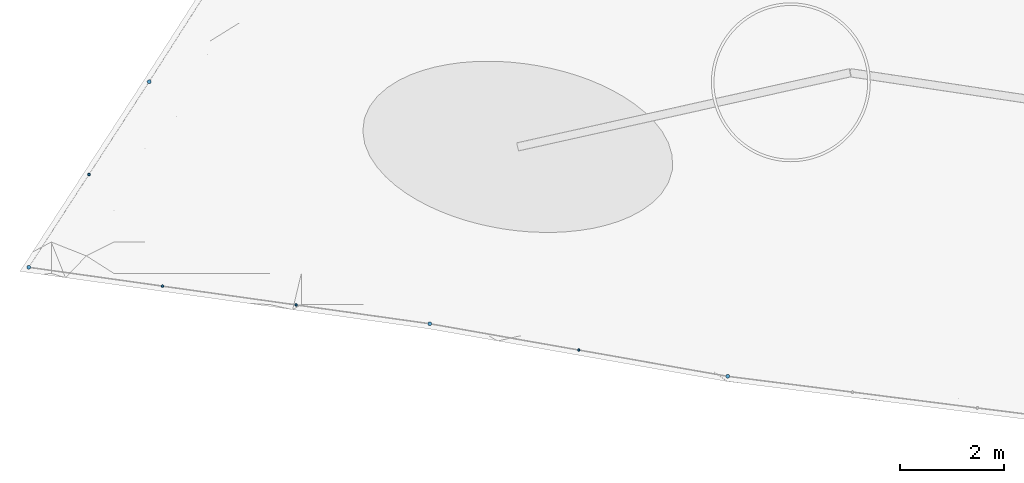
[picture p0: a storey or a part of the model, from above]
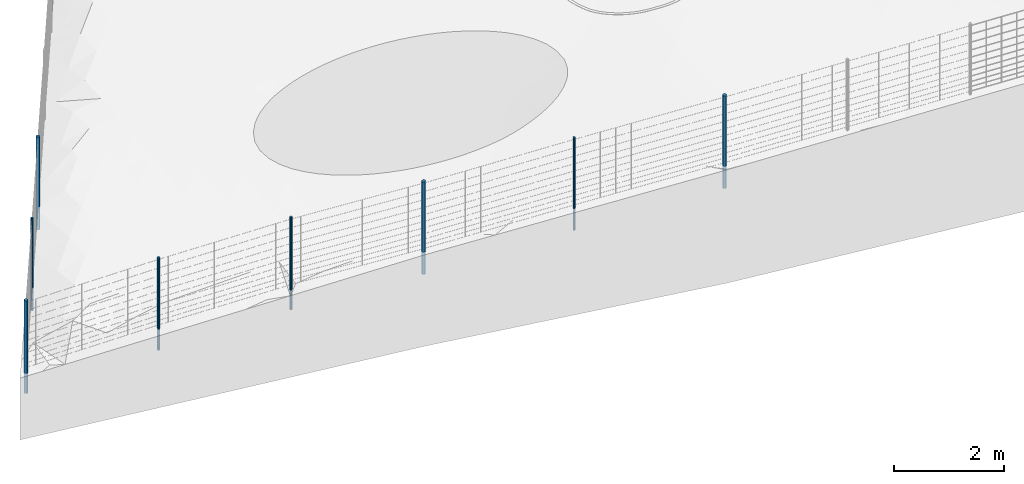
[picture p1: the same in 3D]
Properties of the parts of a building model (IFC4), part 1 of 3

# File
Description: ViewDefinition [CoordinationView]
File name: Casa_Sobreposta_Implantada.ifc
Time: 2026-10-02T16:19:36
Written by: IfcOpenShell 0.8.0
Made in: IfcOpenShell 0.8.0

# IfcProject, Casa / Lares · R09 · Estufa
Pset_CasaModel - Design: R09 / estufa / lower hybrid podium and ground-supported parking; ReferenceFile: 260617_CasaDFL_Estrutura_Terreno.ifc; ModelStatus: DESIGN_STUDY; North: Survey grid +Y; Ramp: No exterior pedestrian ramp or vehicular bridge; EngineeringStatus: Member sizes, foundations, connections, bracing and environmental performance not verified; GroundFFL_m: 14.65; AreaLimit_m2: 250; CountedGeometricArea_m2: 181.073; GreenhouseExcludedByUser: yes; UpperFinishedFloor_m: 17.89; BalconiesExcludedByClient: yes; CoveredGroundBalcony_m2: 56.7788; PlanningComplianceEstablished: no; AreaBasis: Client-confirmed 250 m2 allowance: parking, cistern, balconies and open greenhouse excluded; enclosed upper rooms and stair enclosures count. Any storage would count. Geometric study, no independent PDM verification.

# IfcSite, Lares · Rua das Mercês · artigo 4771
Pset_SurveySource - File: GN_09.26_213 Lares.dwg; SHA256: 0bca0a0751148bad1398f92d81b795428f94a57fea5e37dec0e125cea70402a1; Area_m2: 1636.5; BoundaryHandle: 31B; CoordinateReference: PT-TM06 / ETRS89; TerrainStatus: Proposed grading; original survey in separate IFC

# IfcBuilding, Casa Sobreposta
Pset_CasaFloorAssembly - UpperFFL_m: 3.24; JoistUnderside_m: 2.968; JoistDepth_m: 0.24; OSB_m: 0.02; Membrane_m: 0.002; ProtectiveFinish_m: 0.01; Basis: TJI240 + OSB20 from reference; greenhouse waterproofing/finish assumed; imposed loads unverified
Pset_CasaPlacement - GroundFloorSurveyLevel_m: 14.65; UpperFloor: yes; MoveEast_m: 3; MoveSouth_m: 0.5; RotationFromGridEast_deg: -8.5; BoundarySetbackRequired_m: 3; RuleBasis: User project constraint
Pset_CasaRevision09 - Variant: estufa; HybridPodium: yes; ParkingGroundSupported: yes; GroundFFL_m: 14.65; TerraceFFL_m: 14.61; VehicularBridgeLength_m: 0; AccessGabions: no; Cut_m3: 96.4024; Fill_m3: 5.19635; EarthworkExclusions: Topsoil, foundation/service trenches, soil replacement, construction working space and bulking; CoveredGroundBalconyClassification: EXCLUDED_BY_CLIENT; WindCapacityVerified: no

# IfcBuildingStorey (3)
In: Casa Sobreposta
Name | Elevation (m)
00 · Habitação e estacionamento | 14.65
01 · Jardim de inverno | 17.89
-01 · Cisterna sob o terraço | 12.05

# IfcSpace (18)
Pset_CasaProvenance - DesignSource: Casa Sobreposta / configuration.json; ReferenceFile: 260617_CasaDFL_Estrutura_Terreno.ifc; ConstructionBasis: DESIGN_ASSUMPTION; Note: Functional zone from configurator; overlaps with partition footprints removed on ground floor. Not certified usable floor area.
Name | In | PredefinedType | NetFloorArea (m2)
Sala | 00 · Habitação e estacionamento | INTERNAL | 31.359
Cozinha | 00 · Habitação e estacionamento | INTERNAL | 9.94248
Banho | 00 · Habitação e estacionamento | INTERNAL | 7.19804
WC | 00 · Habitação e estacionamento | INTERNAL | 1.231
Serviço | 00 · Habitação e estacionamento | INTERNAL | 4.16058
Acesso IS | 00 · Habitação e estacionamento | INTERNAL | 3.99017
Quarto 1 | 00 · Habitação e estacionamento | INTERNAL | 13.1145
Quarto 2 | 00 · Habitação e estacionamento | INTERNAL | 13.1145
Quarto / escritório | 00 · Habitação e estacionamento | INTERNAL | 37.8909
Circulação | 00 · Habitação e estacionamento | INTERNAL | 18.1139
Estacionamento · 2 lugares | 00 · Habitação e estacionamento | EXTERNAL | 32.55
Galeria sul · balanço 1,50 m | 01 · Jardim de inverno | INTERNAL | 48
Jardim de inverno | 01 · Jardim de inverno | INTERNAL | 47.852
Circulação / estar | 01 · Jardim de inverno | INTERNAL | 68.8278
Banho superior | 01 · Jardim de inverno | INTERNAL | 7.3678
Cultivo / jardim | 01 · Jardim de inverno | INTERNAL | 25.5734
Estar sobre a garagem | 01 · Jardim de inverno | INTERNAL | 21.292
Balanço | 01 · Jardim de inverno | INTERNAL | 25.6

# IfcAnnotation (4)
Pset_CasaProvenance - DesignSource: Casa Sobreposta / configuration.json; ReferenceFile: 260617_CasaDFL_Estrutura_Terreno.ifc; ConstructionBasis: DESIGN_ASSUMPTION
Name | In
Lugar P1 · 2.50 x 5.00 m | 00 · Habitação e estacionamento
Lugar P2 · 2.50 x 5.00 m | 00 · Habitação e estacionamento
Limite levantado · 31B | Lares · Rua das Mercês · artigo 4771
Afastamento de implantação · 3 m | Lares · Rua das Mercês · artigo 4771

# IfcBeam (115)
Pset_CasaProvenance - DesignSource: Casa Sobreposta / configuration.json; ReferenceFile: 260617_CasaDFL_Estrutura_Terreno.ifc
Name | In | Material | ConstructionBasis | Note
TJI240 · 0.065 / -1.15 | 01 · Jardim de inverno | Madeira / Bauholz (2), OSB | ADAPTED_REFERENCE | Composite wood flanges + OSB web; 600 mm study spacing. Reference 44.45 mm width / 9.525 mm web; flanges regularised to 28 mm. Not structurally sized.
TJI240 · 4.065 / -1.15 | 01 · Jardim de inverno | Madeira / Bauholz (2), OSB | ADAPTED_REFERENCE | Composite wood flanges + OSB web; 600 mm study spacing. Reference 44.45 mm width / 9.525 mm web; flanges regularised to 28 mm. Not structurally sized.
TJI240 · 8.065 / -1.15 | 01 · Jardim de inverno | Madeira / Bauholz (2), OSB | ADAPTED_REFERENCE | Composite wood flanges + OSB web; 600 mm study spacing. Reference 44.45 mm width / 9.525 mm web; flanges regularised to 28 mm. Not structurally sized.
TJI240 · 12.065 / -1.15 | 01 · Jardim de inverno | Madeira / Bauholz (2), OSB | ADAPTED_REFERENCE | Composite wood flanges + OSB web; 600 mm study spacing. Reference 44.45 mm width / 9.525 mm web; flanges regularised to 28 mm. Not structurally sized.
TJI240 · 16.065 / -1.15 | 01 · Jardim de inverno | Madeira / Bauholz (2), OSB | ADAPTED_REFERENCE | Composite wood flanges + OSB web; 600 mm study spacing. Reference 44.45 mm width / 9.525 mm web; flanges regularised to 28 mm. Not structurally sized.
TJI240 · 20.065 / -1.15 | 01 · Jardim de inverno | Madeira / Bauholz (2), OSB | ADAPTED_REFERENCE | Composite wood flanges + OSB web; 600 mm study spacing. Reference 44.45 mm width / 9.525 mm web; flanges regularised to 28 mm. Not structurally sized.
TJI240 · 24.065 / -1.15 | 01 · Jardim de inverno | Madeira / Bauholz (2), OSB | ADAPTED_REFERENCE | Composite wood flanges + OSB web; 600 mm study spacing. Reference 44.45 mm width / 9.525 mm web; flanges regularised to 28 mm. Not structurally sized.
TJI240 · 28.065 / -1.15 | 01 · Jardim de inverno | Madeira / Bauholz (2), OSB | ADAPTED_REFERENCE | Composite wood flanges + OSB web; 600 mm study spacing. Reference 44.45 mm width / 9.525 mm web; flanges regularised to 28 mm. Not structurally sized.
TJI240 · 0.065 / -0.55 | 01 · Jardim de inverno | Madeira / Bauholz (2), OSB | ADAPTED_REFERENCE | Composite wood flanges + OSB web; 600 mm study spacing. Reference 44.45 mm width / 9.525 mm web; flanges regularised to 28 mm. Not structurally sized.
TJI240 · 4.065 / -0.55 | 01 · Jardim de inverno | Madeira / Bauholz (2), OSB | ADAPTED_REFERENCE | Composite wood flanges + OSB web; 600 mm study spacing. Reference 44.45 mm width / 9.525 mm web; flanges regularised to 28 mm. Not structurally sized.
TJI240 · 8.065 / -0.55 | 01 · Jardim de inverno | Madeira / Bauholz (2), OSB | ADAPTED_REFERENCE | Composite wood flanges + OSB web; 600 mm study spacing. Reference 44.45 mm width / 9.525 mm web; flanges regularised to 28 mm. Not structurally sized.
TJI240 · 12.065 / -0.55 | 01 · Jardim de inverno | Madeira / Bauholz (2), OSB | ADAPTED_REFERENCE | Composite wood flanges + OSB web; 600 mm study spacing. Reference 44.45 mm width / 9.525 mm web; flanges regularised to 28 mm. Not structurally sized.
TJI240 · 16.065 / -0.55 | 01 · Jardim de inverno | Madeira / Bauholz (2), OSB | ADAPTED_REFERENCE | Composite wood flanges + OSB web; 600 mm study spacing. Reference 44.45 mm width / 9.525 mm web; flanges regularised to 28 mm. Not structurally sized.
TJI240 · 20.065 / -0.55 | 01 · Jardim de inverno | Madeira / Bauholz (2), OSB | ADAPTED_REFERENCE | Composite wood flanges + OSB web; 600 mm study spacing. Reference 44.45 mm width / 9.525 mm web; flanges regularised to 28 mm. Not structurally sized.
TJI240 · 24.065 / -0.55 | 01 · Jardim de inverno | Madeira / Bauholz (2), OSB | ADAPTED_REFERENCE | Composite wood flanges + OSB web; 600 mm study spacing. Reference 44.45 mm width / 9.525 mm web; flanges regularised to 28 mm. Not structurally sized.
TJI240 · 28.065 / -0.55 | 01 · Jardim de inverno | Madeira / Bauholz (2), OSB | ADAPTED_REFERENCE | Composite wood flanges + OSB web; 600 mm study spacing. Reference 44.45 mm width / 9.525 mm web; flanges regularised to 28 mm. Not structurally sized.
TJI240 · 0.065 / 0.05 | 01 · Jardim de inverno | Madeira / Bauholz (2), OSB | ADAPTED_REFERENCE | Composite wood flanges + OSB web; 600 mm study spacing. Reference 44.45 mm width / 9.525 mm web; flanges regularised to 28 mm. Not structurally sized.
TJI240 · 4.065 / 0.05 | 01 · Jardim de inverno | Madeira / Bauholz (2), OSB | ADAPTED_REFERENCE | Composite wood flanges + OSB web; 600 mm study spacing. Reference 44.45 mm width / 9.525 mm web; flanges regularised to 28 mm. Not structurally sized.
TJI240 · 8.065 / 0.05 | 01 · Jardim de inverno | Madeira / Bauholz (2), OSB | ADAPTED_REFERENCE | Composite wood flanges + OSB web; 600 mm study spacing. Reference 44.45 mm width / 9.525 mm web; flanges regularised to 28 mm. Not structurally sized.
TJI240 · 12.065 / 0.05 | 01 · Jardim de inverno | Madeira / Bauholz (2), OSB | ADAPTED_REFERENCE | Composite wood flanges + OSB web; 600 mm study spacing. Reference 44.45 mm width / 9.525 mm web; flanges regularised to 28 mm. Not structurally sized.
TJI240 · 16.065 / 0.05 | 01 · Jardim de inverno | Madeira / Bauholz (2), OSB | ADAPTED_REFERENCE | Composite wood flanges + OSB web; 600 mm study spacing. Reference 44.45 mm width / 9.525 mm web; flanges regularised to 28 mm. Not structurally sized.
TJI240 · 20.065 / 0.05 | 01 · Jardim de inverno | Madeira / Bauholz (2), OSB | ADAPTED_REFERENCE | Composite wood flanges + OSB web; 600 mm study spacing. Reference 44.45 mm width / 9.525 mm web; flanges regularised to 28 mm. Not structurally sized.
TJI240 · 24.065 / 0.05 | 01 · Jardim de inverno | Madeira / Bauholz (2), OSB | ADAPTED_REFERENCE | Composite wood flanges + OSB web; 600 mm study spacing. Reference 44.45 mm width / 9.525 mm web; flanges regularised to 28 mm. Not structurally sized.
TJI240 · 28.065 / 0.05 | 01 · Jardim de inverno | Madeira / Bauholz (2), OSB | ADAPTED_REFERENCE | Composite wood flanges + OSB web; 600 mm study spacing. Reference 44.45 mm width / 9.525 mm web; flanges regularised to 28 mm. Not structurally sized.
TJI240 · 0.065 / 0.65 | 01 · Jardim de inverno | Madeira / Bauholz (2), OSB | ADAPTED_REFERENCE | Composite wood flanges + OSB web; 600 mm study spacing. Reference 44.45 mm width / 9.525 mm web; flanges regularised to 28 mm. Not structurally sized.
TJI240 · 4.065 / 0.65 | 01 · Jardim de inverno | Madeira / Bauholz (2), OSB | ADAPTED_REFERENCE | Composite wood flanges + OSB web; 600 mm study spacing. Reference 44.45 mm width / 9.525 mm web; flanges regularised to 28 mm. Not structurally sized.
TJI240 · 8.065 / 0.65 | 01 · Jardim de inverno | Madeira / Bauholz (2), OSB | ADAPTED_REFERENCE | Composite wood flanges + OSB web; 600 mm study spacing. Reference 44.45 mm width / 9.525 mm web; flanges regularised to 28 mm. Not structurally sized.
TJI240 · 12.065 / 0.65 | 01 · Jardim de inverno | Madeira / Bauholz (2), OSB | ADAPTED_REFERENCE | Composite wood flanges + OSB web; 600 mm study spacing. Reference 44.45 mm width / 9.525 mm web; flanges regularised to 28 mm. Not structurally sized.
TJI240 · 16.065 / 0.65 | 01 · Jardim de inverno | Madeira / Bauholz (2), OSB | ADAPTED_REFERENCE | Composite wood flanges + OSB web; 600 mm study spacing. Reference 44.45 mm width / 9.525 mm web; flanges regularised to 28 mm. Not structurally sized.
TJI240 · 20.065 / 0.65 | 01 · Jardim de inverno | Madeira / Bauholz (2), OSB | ADAPTED_REFERENCE | Composite wood flanges + OSB web; 600 mm study spacing. Reference 44.45 mm width / 9.525 mm web; flanges regularised to 28 mm. Not structurally sized.
TJI240 · 24.065 / 0.65 | 01 · Jardim de inverno | Madeira / Bauholz (2), OSB | ADAPTED_REFERENCE | Composite wood flanges + OSB web; 600 mm study spacing. Reference 44.45 mm width / 9.525 mm web; flanges regularised to 28 mm. Not structurally sized.
TJI240 · 28.065 / 0.65 | 01 · Jardim de inverno | Madeira / Bauholz (2), OSB | ADAPTED_REFERENCE | Composite wood flanges + OSB web; 600 mm study spacing. Reference 44.45 mm width / 9.525 mm web; flanges regularised to 28 mm. Not structurally sized.
TJI240 · 0.970 / 1.25 | 01 · Jardim de inverno | Madeira / Bauholz (2), OSB | ADAPTED_REFERENCE | Composite wood flanges + OSB web; 600 mm study spacing. Reference 44.45 mm width / 9.525 mm web; flanges regularised to 28 mm. Not structurally sized.
TJI240 · 4.065 / 1.25 | 01 · Jardim de inverno | Madeira / Bauholz (2), OSB | ADAPTED_REFERENCE | Composite wood flanges + OSB web; 600 mm study spacing. Reference 44.45 mm width / 9.525 mm web; flanges regularised to 28 mm. Not structurally sized.
TJI240 · 8.065 / 1.25 | 01 · Jardim de inverno | Madeira / Bauholz (2), OSB | ADAPTED_REFERENCE | Composite wood flanges + OSB web; 600 mm study spacing. Reference 44.45 mm width / 9.525 mm web; flanges regularised to 28 mm. Not structurally sized.
TJI240 · 12.065 / 1.25 | 01 · Jardim de inverno | Madeira / Bauholz (2), OSB | ADAPTED_REFERENCE | Composite wood flanges + OSB web; 600 mm study spacing. Reference 44.45 mm width / 9.525 mm web; flanges regularised to 28 mm. Not structurally sized.
TJI240 · 16.065 / 1.25 | 01 · Jardim de inverno | Madeira / Bauholz (2), OSB | ADAPTED_REFERENCE | Composite wood flanges + OSB web; 600 mm study spacing. Reference 44.45 mm width / 9.525 mm web; flanges regularised to 28 mm. Not structurally sized.
TJI240 · 20.065 / 1.25 | 01 · Jardim de inverno | Madeira / Bauholz (2), OSB | ADAPTED_REFERENCE | Composite wood flanges + OSB web; 600 mm study spacing. Reference 44.45 mm width / 9.525 mm web; flanges regularised to 28 mm. Not structurally sized.
TJI240 · 25.040 / 1.25 | 01 · Jardim de inverno | Madeira / Bauholz (2), OSB | ADAPTED_REFERENCE | Composite wood flanges + OSB web; 600 mm study spacing. Reference 44.45 mm width / 9.525 mm web; flanges regularised to 28 mm. Not structurally sized.
TJI240 · 28.065 / 1.25 | 01 · Jardim de inverno | Madeira / Bauholz (2), OSB | ADAPTED_REFERENCE | Composite wood flanges + OSB web; 600 mm study spacing. Reference 44.45 mm width / 9.525 mm web; flanges regularised to 28 mm. Not structurally sized.
TJI240 · 0.970 / 1.85 | 01 · Jardim de inverno | Madeira / Bauholz (2), OSB | ADAPTED_REFERENCE | Composite wood flanges + OSB web; 600 mm study spacing. Reference 44.45 mm width / 9.525 mm web; flanges regularised to 28 mm. Not structurally sized.
TJI240 · 4.065 / 1.85 | 01 · Jardim de inverno | Madeira / Bauholz (2), OSB | ADAPTED_REFERENCE | Composite wood flanges + OSB web; 600 mm study spacing. Reference 44.45 mm width / 9.525 mm web; flanges regularised to 28 mm. Not structurally sized.
TJI240 · 8.065 / 1.85 | 01 · Jardim de inverno | Madeira / Bauholz (2), OSB | ADAPTED_REFERENCE | Composite wood flanges + OSB web; 600 mm study spacing. Reference 44.45 mm width / 9.525 mm web; flanges regularised to 28 mm. Not structurally sized.
TJI240 · 12.065 / 1.85 | 01 · Jardim de inverno | Madeira / Bauholz (2), OSB | ADAPTED_REFERENCE | Composite wood flanges + OSB web; 600 mm study spacing. Reference 44.45 mm width / 9.525 mm web; flanges regularised to 28 mm. Not structurally sized.
TJI240 · 16.065 / 1.85 | 01 · Jardim de inverno | Madeira / Bauholz (2), OSB | ADAPTED_REFERENCE | Composite wood flanges + OSB web; 600 mm study spacing. Reference 44.45 mm width / 9.525 mm web; flanges regularised to 28 mm. Not structurally sized.
TJI240 · 20.065 / 1.85 | 01 · Jardim de inverno | Madeira / Bauholz (2), OSB | ADAPTED_REFERENCE | Composite wood flanges + OSB web; 600 mm study spacing. Reference 44.45 mm width / 9.525 mm web; flanges regularised to 28 mm. Not structurally sized.
TJI240 · 25.040 / 1.85 | 01 · Jardim de inverno | Madeira / Bauholz (2), OSB | ADAPTED_REFERENCE | Composite wood flanges + OSB web; 600 mm study spacing. Reference 44.45 mm width / 9.525 mm web; flanges regularised to 28 mm. Not structurally sized.
TJI240 · 28.065 / 1.85 | 01 · Jardim de inverno | Madeira / Bauholz (2), OSB | ADAPTED_REFERENCE | Composite wood flanges + OSB web; 600 mm study spacing. Reference 44.45 mm width / 9.525 mm web; flanges regularised to 28 mm. Not structurally sized.
TJI240 · 0.970 / 2.45 | 01 · Jardim de inverno | Madeira / Bauholz (2), OSB | ADAPTED_REFERENCE | Composite wood flanges + OSB web; 600 mm study spacing. Reference 44.45 mm width / 9.525 mm web; flanges regularised to 28 mm. Not structurally sized.
TJI240 · 4.065 / 2.45 | 01 · Jardim de inverno | Madeira / Bauholz (2), OSB | ADAPTED_REFERENCE | Composite wood flanges + OSB web; 600 mm study spacing. Reference 44.45 mm width / 9.525 mm web; flanges regularised to 28 mm. Not structurally sized.
TJI240 · 8.065 / 2.45 | 01 · Jardim de inverno | Madeira / Bauholz (2), OSB | ADAPTED_REFERENCE | Composite wood flanges + OSB web; 600 mm study spacing. Reference 44.45 mm width / 9.525 mm web; flanges regularised to 28 mm. Not structurally sized.
TJI240 · 12.065 / 2.45 | 01 · Jardim de inverno | Madeira / Bauholz (2), OSB | ADAPTED_REFERENCE | Composite wood flanges + OSB web; 600 mm study spacing. Reference 44.45 mm width / 9.525 mm web; flanges regularised to 28 mm. Not structurally sized.
TJI240 · 16.065 / 2.45 | 01 · Jardim de inverno | Madeira / Bauholz (2), OSB | ADAPTED_REFERENCE | Composite wood flanges + OSB web; 600 mm study spacing. Reference 44.45 mm width / 9.525 mm web; flanges regularised to 28 mm. Not structurally sized.
TJI240 · 20.065 / 2.45 | 01 · Jardim de inverno | Madeira / Bauholz (2), OSB | ADAPTED_REFERENCE | Composite wood flanges + OSB web; 600 mm study spacing. Reference 44.45 mm width / 9.525 mm web; flanges regularised to 28 mm. Not structurally sized.
TJI240 · 25.040 / 2.45 | 01 · Jardim de inverno | Madeira / Bauholz (2), OSB | ADAPTED_REFERENCE | Composite wood flanges + OSB web; 600 mm study spacing. Reference 44.45 mm width / 9.525 mm web; flanges regularised to 28 mm. Not structurally sized.
TJI240 · 28.065 / 2.45 | 01 · Jardim de inverno | Madeira / Bauholz (2), OSB | ADAPTED_REFERENCE | Composite wood flanges + OSB web; 600 mm study spacing. Reference 44.45 mm width / 9.525 mm web; flanges regularised to 28 mm. Not structurally sized.
TJI240 · 0.970 / 3.05 | 01 · Jardim de inverno | Madeira / Bauholz (2), OSB | ADAPTED_REFERENCE | Composite wood flanges + OSB web; 600 mm study spacing. Reference 44.45 mm width / 9.525 mm web; flanges regularised to 28 mm. Not structurally sized.
TJI240 · 4.065 / 3.05 | 01 · Jardim de inverno | Madeira / Bauholz (2), OSB | ADAPTED_REFERENCE | Composite wood flanges + OSB web; 600 mm study spacing. Reference 44.45 mm width / 9.525 mm web; flanges regularised to 28 mm. Not structurally sized.
TJI240 · 8.065 / 3.05 | 01 · Jardim de inverno | Madeira / Bauholz (2), OSB | ADAPTED_REFERENCE | Composite wood flanges + OSB web; 600 mm study spacing. Reference 44.45 mm width / 9.525 mm web; flanges regularised to 28 mm. Not structurally sized.
TJI240 · 12.065 / 3.05 | 01 · Jardim de inverno | Madeira / Bauholz (2), OSB | ADAPTED_REFERENCE | Composite wood flanges + OSB web; 600 mm study spacing. Reference 44.45 mm width / 9.525 mm web; flanges regularised to 28 mm. Not structurally sized.
TJI240 · 16.065 / 3.05 | 01 · Jardim de inverno | Madeira / Bauholz (2), OSB | ADAPTED_REFERENCE | Composite wood flanges + OSB web; 600 mm study spacing. Reference 44.45 mm width / 9.525 mm web; flanges regularised to 28 mm. Not structurally sized.
TJI240 · 20.065 / 3.05 | 01 · Jardim de inverno | Madeira / Bauholz (2), OSB | ADAPTED_REFERENCE | Composite wood flanges + OSB web; 600 mm study spacing. Reference 44.45 mm width / 9.525 mm web; flanges regularised to 28 mm. Not structurally sized.
TJI240 · 25.040 / 3.05 | 01 · Jardim de inverno | Madeira / Bauholz (2), OSB | ADAPTED_REFERENCE | Composite wood flanges + OSB web; 600 mm study spacing. Reference 44.45 mm width / 9.525 mm web; flanges regularised to 28 mm. Not structurally sized.
TJI240 · 28.065 / 3.05 | 01 · Jardim de inverno | Madeira / Bauholz (2), OSB | ADAPTED_REFERENCE | Composite wood flanges + OSB web; 600 mm study spacing. Reference 44.45 mm width / 9.525 mm web; flanges regularised to 28 mm. Not structurally sized.
TJI240 · 0.970 / 3.65 | 01 · Jardim de inverno | Madeira / Bauholz (2), OSB | ADAPTED_REFERENCE | Composite wood flanges + OSB web; 600 mm study spacing. Reference 44.45 mm width / 9.525 mm web; flanges regularised to 28 mm. Not structurally sized.
TJI240 · 4.065 / 3.65 | 01 · Jardim de inverno | Madeira / Bauholz (2), OSB | ADAPTED_REFERENCE | Composite wood flanges + OSB web; 600 mm study spacing. Reference 44.45 mm width / 9.525 mm web; flanges regularised to 28 mm. Not structurally sized.
TJI240 · 8.065 / 3.65 | 01 · Jardim de inverno | Madeira / Bauholz (2), OSB | ADAPTED_REFERENCE | Composite wood flanges + OSB web; 600 mm study spacing. Reference 44.45 mm width / 9.525 mm web; flanges regularised to 28 mm. Not structurally sized.
TJI240 · 12.065 / 3.65 | 01 · Jardim de inverno | Madeira / Bauholz (2), OSB | ADAPTED_REFERENCE | Composite wood flanges + OSB web; 600 mm study spacing. Reference 44.45 mm width / 9.525 mm web; flanges regularised to 28 mm. Not structurally sized.
TJI240 · 16.065 / 3.65 | 01 · Jardim de inverno | Madeira / Bauholz (2), OSB | ADAPTED_REFERENCE | Composite wood flanges + OSB web; 600 mm study spacing. Reference 44.45 mm width / 9.525 mm web; flanges regularised to 28 mm. Not structurally sized.
TJI240 · 20.065 / 3.65 | 01 · Jardim de inverno | Madeira / Bauholz (2), OSB | ADAPTED_REFERENCE | Composite wood flanges + OSB web; 600 mm study spacing. Reference 44.45 mm width / 9.525 mm web; flanges regularised to 28 mm. Not structurally sized.
TJI240 · 25.040 / 3.65 | 01 · Jardim de inverno | Madeira / Bauholz (2), OSB | ADAPTED_REFERENCE | Composite wood flanges + OSB web; 600 mm study spacing. Reference 44.45 mm width / 9.525 mm web; flanges regularised to 28 mm. Not structurally sized.
TJI240 · 28.065 / 3.65 | 01 · Jardim de inverno | Madeira / Bauholz (2), OSB | ADAPTED_REFERENCE | Composite wood flanges + OSB web; 600 mm study spacing. Reference 44.45 mm width / 9.525 mm web; flanges regularised to 28 mm. Not structurally sized.
TJI240 · 0.970 / 4.25 | 01 · Jardim de inverno | Madeira / Bauholz (2), OSB | ADAPTED_REFERENCE | Composite wood flanges + OSB web; 600 mm study spacing. Reference 44.45 mm width / 9.525 mm web; flanges regularised to 28 mm. Not structurally sized.
TJI240 · 4.065 / 4.25 | 01 · Jardim de inverno | Madeira / Bauholz (2), OSB | ADAPTED_REFERENCE | Composite wood flanges + OSB web; 600 mm study spacing. Reference 44.45 mm width / 9.525 mm web; flanges regularised to 28 mm. Not structurally sized.
TJI240 · 8.065 / 4.25 | 01 · Jardim de inverno | Madeira / Bauholz (2), OSB | ADAPTED_REFERENCE | Composite wood flanges + OSB web; 600 mm study spacing. Reference 44.45 mm width / 9.525 mm web; flanges regularised to 28 mm. Not structurally sized.
TJI240 · 12.065 / 4.25 | 01 · Jardim de inverno | Madeira / Bauholz (2), OSB | ADAPTED_REFERENCE | Composite wood flanges + OSB web; 600 mm study spacing. Reference 44.45 mm width / 9.525 mm web; flanges regularised to 28 mm. Not structurally sized.
TJI240 · 16.065 / 4.25 | 01 · Jardim de inverno | Madeira / Bauholz (2), OSB | ADAPTED_REFERENCE | Composite wood flanges + OSB web; 600 mm study spacing. Reference 44.45 mm width / 9.525 mm web; flanges regularised to 28 mm. Not structurally sized.
TJI240 · 20.065 / 4.25 | 01 · Jardim de inverno | Madeira / Bauholz (2), OSB | ADAPTED_REFERENCE | Composite wood flanges + OSB web; 600 mm study spacing. Reference 44.45 mm width / 9.525 mm web; flanges regularised to 28 mm. Not structurally sized.
TJI240 · 25.040 / 4.25 | 01 · Jardim de inverno | Madeira / Bauholz (2), OSB | ADAPTED_REFERENCE | Composite wood flanges + OSB web; 600 mm study spacing. Reference 44.45 mm width / 9.525 mm web; flanges regularised to 28 mm. Not structurally sized.
TJI240 · 28.065 / 4.25 | 01 · Jardim de inverno | Madeira / Bauholz (2), OSB | ADAPTED_REFERENCE | Composite wood flanges + OSB web; 600 mm study spacing. Reference 44.45 mm width / 9.525 mm web; flanges regularised to 28 mm. Not structurally sized.
TJI240 · 0.970 / 4.85 | 01 · Jardim de inverno | Madeira / Bauholz (2), OSB | ADAPTED_REFERENCE | Composite wood flanges + OSB web; 600 mm study spacing. Reference 44.45 mm width / 9.525 mm web; flanges regularised to 28 mm. Not structurally sized.
TJI240 · 4.065 / 4.85 | 01 · Jardim de inverno | Madeira / Bauholz (2), OSB | ADAPTED_REFERENCE | Composite wood flanges + OSB web; 600 mm study spacing. Reference 44.45 mm width / 9.525 mm web; flanges regularised to 28 mm. Not structurally sized.
TJI240 · 8.065 / 4.85 | 01 · Jardim de inverno | Madeira / Bauholz (2), OSB | ADAPTED_REFERENCE | Composite wood flanges + OSB web; 600 mm study spacing. Reference 44.45 mm width / 9.525 mm web; flanges regularised to 28 mm. Not structurally sized.
TJI240 · 12.065 / 4.85 | 01 · Jardim de inverno | Madeira / Bauholz (2), OSB | ADAPTED_REFERENCE | Composite wood flanges + OSB web; 600 mm study spacing. Reference 44.45 mm width / 9.525 mm web; flanges regularised to 28 mm. Not structurally sized.
TJI240 · 16.065 / 4.85 | 01 · Jardim de inverno | Madeira / Bauholz (2), OSB | ADAPTED_REFERENCE | Composite wood flanges + OSB web; 600 mm study spacing. Reference 44.45 mm width / 9.525 mm web; flanges regularised to 28 mm. Not structurally sized.
TJI240 · 20.065 / 4.85 | 01 · Jardim de inverno | Madeira / Bauholz (2), OSB | ADAPTED_REFERENCE | Composite wood flanges + OSB web; 600 mm study spacing. Reference 44.45 mm width / 9.525 mm web; flanges regularised to 28 mm. Not structurally sized.
TJI240 · 25.040 / 4.85 | 01 · Jardim de inverno | Madeira / Bauholz (2), OSB | ADAPTED_REFERENCE | Composite wood flanges + OSB web; 600 mm study spacing. Reference 44.45 mm width / 9.525 mm web; flanges regularised to 28 mm. Not structurally sized.
TJI240 · 28.065 / 4.85 | 01 · Jardim de inverno | Madeira / Bauholz (2), OSB | ADAPTED_REFERENCE | Composite wood flanges + OSB web; 600 mm study spacing. Reference 44.45 mm width / 9.525 mm web; flanges regularised to 28 mm. Not structurally sized.
TJI240 · 0.970 / 5.45 | 01 · Jardim de inverno | Madeira / Bauholz (2), OSB | ADAPTED_REFERENCE | Composite wood flanges + OSB web; 600 mm study spacing. Reference 44.45 mm width / 9.525 mm web; flanges regularised to 28 mm. Not structurally sized.
TJI240 · 4.065 / 5.45 | 01 · Jardim de inverno | Madeira / Bauholz (2), OSB | ADAPTED_REFERENCE | Composite wood flanges + OSB web; 600 mm study spacing. Reference 44.45 mm width / 9.525 mm web; flanges regularised to 28 mm. Not structurally sized.
TJI240 · 8.065 / 5.45 | 01 · Jardim de inverno | Madeira / Bauholz (2), OSB | ADAPTED_REFERENCE | Composite wood flanges + OSB web; 600 mm study spacing. Reference 44.45 mm width / 9.525 mm web; flanges regularised to 28 mm. Not structurally sized.
TJI240 · 12.065 / 5.45 | 01 · Jardim de inverno | Madeira / Bauholz (2), OSB | ADAPTED_REFERENCE | Composite wood flanges + OSB web; 600 mm study spacing. Reference 44.45 mm width / 9.525 mm web; flanges regularised to 28 mm. Not structurally sized.
TJI240 · 16.065 / 5.45 | 01 · Jardim de inverno | Madeira / Bauholz (2), OSB | ADAPTED_REFERENCE | Composite wood flanges + OSB web; 600 mm study spacing. Reference 44.45 mm width / 9.525 mm web; flanges regularised to 28 mm. Not structurally sized.
TJI240 · 20.065 / 5.45 | 01 · Jardim de inverno | Madeira / Bauholz (2), OSB | ADAPTED_REFERENCE | Composite wood flanges + OSB web; 600 mm study spacing. Reference 44.45 mm width / 9.525 mm web; flanges regularised to 28 mm. Not structurally sized.
TJI240 · 25.040 / 5.45 | 01 · Jardim de inverno | Madeira / Bauholz (2), OSB | ADAPTED_REFERENCE | Composite wood flanges + OSB web; 600 mm study spacing. Reference 44.45 mm width / 9.525 mm web; flanges regularised to 28 mm. Not structurally sized.
TJI240 · 28.065 / 5.45 | 01 · Jardim de inverno | Madeira / Bauholz (2), OSB | ADAPTED_REFERENCE | Composite wood flanges + OSB web; 600 mm study spacing. Reference 44.45 mm width / 9.525 mm web; flanges regularised to 28 mm. Not structurally sized.
TJI240 · 0.065 / 6.05 | 01 · Jardim de inverno | Madeira / Bauholz (2), OSB | ADAPTED_REFERENCE | Composite wood flanges + OSB web; 600 mm study spacing. Reference 44.45 mm width / 9.525 mm web; flanges regularised to 28 mm. Not structurally sized.
TJI240 · 4.065 / 6.05 | 01 · Jardim de inverno | Madeira / Bauholz (2), OSB | ADAPTED_REFERENCE | Composite wood flanges + OSB web; 600 mm study spacing. Reference 44.45 mm width / 9.525 mm web; flanges regularised to 28 mm. Not structurally sized.
TJI240 · 8.065 / 6.05 | 01 · Jardim de inverno | Madeira / Bauholz (2), OSB | ADAPTED_REFERENCE | Composite wood flanges + OSB web; 600 mm study spacing. Reference 44.45 mm width / 9.525 mm web; flanges regularised to 28 mm. Not structurally sized.
TJI240 · 12.065 / 6.05 | 01 · Jardim de inverno | Madeira / Bauholz (2), OSB | ADAPTED_REFERENCE | Composite wood flanges + OSB web; 600 mm study spacing. Reference 44.45 mm width / 9.525 mm web; flanges regularised to 28 mm. Not structurally sized.
TJI240 · 16.065 / 6.05 | 01 · Jardim de inverno | Madeira / Bauholz (2), OSB | ADAPTED_REFERENCE | Composite wood flanges + OSB web; 600 mm study spacing. Reference 44.45 mm width / 9.525 mm web; flanges regularised to 28 mm. Not structurally sized.
TJI240 · 20.065 / 6.05 | 01 · Jardim de inverno | Madeira / Bauholz (2), OSB | ADAPTED_REFERENCE | Composite wood flanges + OSB web; 600 mm study spacing. Reference 44.45 mm width / 9.525 mm web; flanges regularised to 28 mm. Not structurally sized.
TJI240 · 24.065 / 6.05 | 01 · Jardim de inverno | Madeira / Bauholz (2), OSB | ADAPTED_REFERENCE | Composite wood flanges + OSB web; 600 mm study spacing. Reference 44.45 mm width / 9.525 mm web; flanges regularised to 28 mm. Not structurally sized.
TJI240 · 28.065 / 6.05 | 01 · Jardim de inverno | Madeira / Bauholz (2), OSB | ADAPTED_REFERENCE | Composite wood flanges + OSB web; 600 mm study spacing. Reference 44.45 mm width / 9.525 mm web; flanges regularised to 28 mm. Not structurally sized.
8 x Pódio suspenso · viga transversal | 00 · Habitação e estacionamento | Betão armado / Stahlbeton | DESIGN_ASSUMPTION
3 x Pódio suspenso · viga longitudinal | 00 · Habitação e estacionamento | Betão armado / Stahlbeton | DESIGN_ASSUMPTION

# IfcBeam: IPE240 / steel (46)
Type - Material: Aço pintado / Stahl lackiert
Pset_CasaProvenance - DesignSource: Casa Sobreposta / configuration.json; ReferenceFile: 260617_CasaDFL_Estrutura_Terreno.ifc; ConstructionBasis: ADAPTED_REFERENCE; Note: Reference section; spans, stability and connections require design.
Name | In
Viga longitudinal 0 / 0.12 | 01 · Jardim de inverno
Viga longitudinal 4 / 0.12 | 01 · Jardim de inverno
Viga longitudinal 8 / 0.12 | 01 · Jardim de inverno
Viga longitudinal 12 / 0.12 | 01 · Jardim de inverno
Viga longitudinal 16 / 0.12 | 01 · Jardim de inverno
Viga longitudinal 20 / 0.12 | 01 · Jardim de inverno
Viga longitudinal 24 / 0.12 | 01 · Jardim de inverno
Viga longitudinal 28 / 0.12 | 01 · Jardim de inverno
Viga longitudinal 0 / 6.28 | 01 · Jardim de inverno
Viga longitudinal 4 / 6.28 | 01 · Jardim de inverno
Viga longitudinal 8 / 6.28 | 01 · Jardim de inverno
Viga longitudinal 12 / 6.28 | 01 · Jardim de inverno
Viga longitudinal 16 / 6.28 | 01 · Jardim de inverno
Viga longitudinal 20 / 6.28 | 01 · Jardim de inverno
Viga longitudinal 24 / 6.28 | 01 · Jardim de inverno
Viga longitudinal 28 / 6.28 | 01 · Jardim de inverno
Viga longitudinal 0 / -1.44 | 01 · Jardim de inverno
Viga longitudinal 4 / -1.44 | 01 · Jardim de inverno
Viga longitudinal 8 / -1.44 | 01 · Jardim de inverno
Viga longitudinal 12 / -1.44 | 01 · Jardim de inverno
Viga longitudinal 16 / -1.44 | 01 · Jardim de inverno
Viga longitudinal 20 / -1.44 | 01 · Jardim de inverno
Viga longitudinal 24 / -1.44 | 01 · Jardim de inverno
Viga longitudinal 28 / -1.44 | 01 · Jardim de inverno
2 x Viga transversal eixo 0 | 01 · Jardim de inverno
Viga transversal eixo 4 | 01 · Jardim de inverno
Viga transversal eixo 8 | 01 · Jardim de inverno
Viga transversal eixo 12 | 01 · Jardim de inverno
Viga transversal eixo 16 | 01 · Jardim de inverno
Viga transversal eixo 20 | 01 · Jardim de inverno
Viga transversal eixo 24 | 01 · Jardim de inverno
Viga transversal eixo 28 | 01 · Jardim de inverno
Viga transversal eixo 32 | 01 · Jardim de inverno
2 x Longarina do vão 1 | 01 · Jardim de inverno
2 x Cabeceira do vão 1 | 01 · Jardim de inverno
2 x Longarina do vão 2 | 01 · Jardim de inverno
2 x Cabeceira do vão 2 | 01 · Jardim de inverno
2 x Varanda · viga de bordo | 00 · Habitação e estacionamento
2 x Varanda · viga transversal | 00 · Habitação e estacionamento

# IfcBeam: RHS100x60x4 / steel (4)
In: 00 · Habitação e estacionamento
Type - Material: Aço pintado / Stahl lackiert
Pset_CasaProvenance - DesignSource: Casa Sobreposta / configuration.json; ReferenceFile: 260617_CasaDFL_Estrutura_Terreno.ifc; ConstructionBasis: DESIGN_ASSUMPTION; Note: Reference section; spans, stability and connections require design.

# IfcBuildingElementProxy: Acesso · caixa de retenção de sedimentos (2)
In: Lares · Rua das Mercês · artigo 4771
PredefinedType: USERDEFINED; Material: Caleiras · betão
Pset_CasaProvenance - DesignSource: Casa Sobreposta / configuration.json; ReferenceFile: 260617_CasaDFL_Estrutura_Terreno.ifc; ConstructionBasis: DESIGN_ASSUMPTION

# IfcBuildingElementProxy: Acesso · dreno lateral raso · leito drenante (74)
In: Lares · Rua das Mercês · artigo 4771
PredefinedType: USERDEFINED; Material: Brita drenante
Pset_CasaProvenance - DesignSource: Casa Sobreposta / configuration.json; ReferenceFile: 260617_CasaDFL_Estrutura_Terreno.ifc; ConstructionBasis: DESIGN_ASSUMPTION; Note: R09 concept geometry; dimensions and connections not structurally verified.

# IfcBuildingElementProxy: Cisterna · água a 2,00 m, hipótese
In: -01 · Cisterna sob o terraço
PredefinedType: USERDEFINED; Material: Água pluvial · nível ilustrativo
Pset_CasaProvenance - DesignSource: Casa Sobreposta / configuration.json; ReferenceFile: 260617_CasaDFL_Estrutura_Terreno.ifc; ConstructionBasis: DESIGN_ASSUMPTION; Note: Illustrative water envelope, not concrete or a certified operating capacity.

# IfcBuildingElementProxy: Interceção · caleira estacionamento · leito drenante (8)
In: Lares · Rua das Mercês · artigo 4771
PredefinedType: USERDEFINED; Material: Brita drenante
Pset_CasaProvenance - DesignSource: Casa Sobreposta / configuration.json; ReferenceFile: 260617_CasaDFL_Estrutura_Terreno.ifc; ConstructionBasis: DESIGN_ASSUMPTION; Note: R09 concept geometry; dimensions and connections not structurally verified.

# IfcBuildingElementProxy: Interceção · caleira rua · leito drenante (8)
In: Lares · Rua das Mercês · artigo 4771
PredefinedType: USERDEFINED; Material: Brita drenante
Pset_CasaProvenance - DesignSource: Casa Sobreposta / configuration.json; ReferenceFile: 260617_CasaDFL_Estrutura_Terreno.ifc; ConstructionBasis: DESIGN_ASSUMPTION; Note: R09 concept geometry; dimensions and connections not structurally verified.

# IfcBuildingElementProxy: Trepadeiras · floreira (10)
In: 00 · Habitação e estacionamento
PredefinedType: USERDEFINED; Material: Betão armado / Stahlbeton
Pset_CasaProvenance - DesignSource: Casa Sobreposta / configuration.json; ReferenceFile: 260617_CasaDFL_Estrutura_Terreno.ifc; ConstructionBasis: DESIGN_ASSUMPTION; Note: Indicative planter; soil volume, irrigation, root space and waterproofing to design.

# IfcColumn (40)
In: 00 · Habitação e estacionamento
Material: Betão armado / Stahlbeton
Pset_CasaProvenance - DesignSource: Casa Sobreposta / configuration.json; ReferenceFile: 260617_CasaDFL_Estrutura_Terreno.ifc
Name | ConstructionBasis
Pedestal 1A · betão 400 x 400 | ADAPTED_REFERENCE
Pedestal 1B · betão 400 x 400 | ADAPTED_REFERENCE
Pedestal 2A · betão 400 x 400 | ADAPTED_REFERENCE
Pedestal 2B · betão 400 x 400 | ADAPTED_REFERENCE
Pedestal 3A · betão 400 x 400 | ADAPTED_REFERENCE
Pedestal 3B · betão 400 x 400 | ADAPTED_REFERENCE
Pedestal 4A · betão 400 x 400 | ADAPTED_REFERENCE
Pedestal 4B · betão 400 x 400 | ADAPTED_REFERENCE
Pedestal 5A · betão 400 x 400 | ADAPTED_REFERENCE
Pedestal 5B · betão 400 x 400 | ADAPTED_REFERENCE
Pedestal 6A · betão 400 x 400 | ADAPTED_REFERENCE
Pedestal 6B · betão 400 x 400 | ADAPTED_REFERENCE
Pedestal 7A · betão 400 x 400 | ADAPTED_REFERENCE
Pedestal 7B · betão 400 x 400 | ADAPTED_REFERENCE
Pedestal 8A · betão 400 x 400 | ADAPTED_REFERENCE
Pedestal 8B · betão 400 x 400 | ADAPTED_REFERENCE
24 x Pódio suspenso · apoio sobre o terreno | DESIGN_ASSUMPTION

# IfcColumn: IPE240 / steel (46)
Type - Material: Aço pintado / Stahl lackiert
Pset_CasaProvenance - DesignSource: Casa Sobreposta / configuration.json; ReferenceFile: 260617_CasaDFL_Estrutura_Terreno.ifc; ConstructionBasis: ADAPTED_REFERENCE; Note: Reference section; spans, stability and connections require design.
Name | In
Pilar 1A · IPE240 | 00 · Habitação e estacionamento
Pilar estufa 1A · IPE240 | 01 · Jardim de inverno
Pilar 1B · IPE240 | 00 · Habitação e estacionamento
Pilar estufa 1B · IPE240 | 01 · Jardim de inverno
Pilar 2A · IPE240 | 00 · Habitação e estacionamento
Pilar estufa 2A · IPE240 | 01 · Jardim de inverno
Pilar 2B · IPE240 | 00 · Habitação e estacionamento
Pilar estufa 2B · IPE240 | 01 · Jardim de inverno
Pilar 3A · IPE240 | 00 · Habitação e estacionamento
Pilar estufa 3A · IPE240 | 01 · Jardim de inverno
Pilar 3B · IPE240 | 00 · Habitação e estacionamento
Pilar estufa 3B · IPE240 | 01 · Jardim de inverno
Pilar 4A · IPE240 | 00 · Habitação e estacionamento
Pilar estufa 4A · IPE240 | 01 · Jardim de inverno
Pilar 4B · IPE240 | 00 · Habitação e estacionamento
Pilar estufa 4B · IPE240 | 01 · Jardim de inverno
Pilar 5A · IPE240 | 00 · Habitação e estacionamento
Pilar estufa 5A · IPE240 | 01 · Jardim de inverno
Pilar 5B · IPE240 | 00 · Habitação e estacionamento
Pilar estufa 5B · IPE240 | 01 · Jardim de inverno
Pilar 6A · IPE240 | 00 · Habitação e estacionamento
Pilar estufa 6A · IPE240 | 01 · Jardim de inverno
Pilar 6B · IPE240 | 00 · Habitação e estacionamento
Pilar estufa 6B · IPE240 | 01 · Jardim de inverno
Pilar 7A · IPE240 | 00 · Habitação e estacionamento
Pilar estufa 7A · IPE240 | 01 · Jardim de inverno
Pilar 7B · IPE240 | 00 · Habitação e estacionamento
Pilar estufa 7B · IPE240 | 01 · Jardim de inverno
Pilar 8A · IPE240 | 00 · Habitação e estacionamento
Pilar estufa 8A · IPE240 | 01 · Jardim de inverno
Pilar 8B · IPE240 | 00 · Habitação e estacionamento
Pilar estufa 8B · IPE240 | 01 · Jardim de inverno
4 x Pérgola · pilar de duplo pé-direito | 00 · Habitação e estacionamento
9 x Projeção estufa · pilar sul ao pódio | 00 · Habitação e estacionamento
Projeção estufa · pilar nascente norte | 00 · Habitação e estacionamento

# IfcColumn: RHS80x60x4 / steel (4)
In: 00 · Habitação e estacionamento
Type - Material: Aço pintado / Stahl lackiert
Pset_CasaProvenance - DesignSource: Casa Sobreposta / configuration.json; ReferenceFile: 260617_CasaDFL_Estrutura_Terreno.ifc; ConstructionBasis: DESIGN_ASSUMPTION; Note: Reference section; spans, stability and connections require design.

# IfcCovering (9)
Pset_CasaProvenance - DesignSource: Casa Sobreposta / configuration.json; ReferenceFile: 260617_CasaDFL_Estrutura_Terreno.ifc; ConstructionBasis: DESIGN_ASSUMPTION
Name | In | PredefinedType | Material
Impermeabilização da estufa · hipótese | 01 · Jardim de inverno | FLOORING | Membrana impermeável — hipótese | Pset_CasaProvenance - Note: Two real stair voids. Light protective finish assumed; drains and waterproof upstands require detailing.
Proteção do pavimento · hipótese | 01 · Jardim de inverno | FLOORING | Pavimento protetor leve — hipótese | Pset_CasaProvenance - Note: Two real stair voids. Light protective finish assumed; drains and waterproof upstands require detailing.
Teto caixa térmica 1 | 01 · Jardim de inverno | CEILING | Pavimento protetor leve — hipótese
Teto caixa térmica 2 | 01 · Jardim de inverno | CEILING | Pavimento protetor leve — hipótese
Cisterna · camada drenante 100 mm | -01 · Cisterna sob o terraço | FLOORING | Brita drenante
Cisterna · impermeabilização poente | -01 · Cisterna sob o terraço | MEMBRANE | Membrana impermeável — hipótese
Cisterna · impermeabilização norte | -01 · Cisterna sob o terraço | MEMBRANE | Membrana impermeável — hipótese
Cisterna · impermeabilização sul | -01 · Cisterna sob o terraço | MEMBRANE | Membrana impermeável — hipótese
Cisterna · impermeabilização nascente | -01 · Cisterna sob o terraço | MEMBRANE | Membrana impermeável — hipótese

# IfcCovering: Cortina interior · 75% (9)
In: 01 · Jardim de inverno
PredefinedType: USERDEFINED; Material: Tecido de sombreamento — hipótese
Pset_CasaProvenance - DesignSource: Casa Sobreposta / configuration.json; ReferenceFile: 260617_CasaDFL_Estrutura_Terreno.ifc; ConstructionBasis: DESIGN_ASSUMPTION; Note: 75% deployment snapshot; fabric specification and cables not sized.

# IfcCovering: Pátio · sombreador têxtil retrátil (2)
In: 00 · Habitação e estacionamento
PredefinedType: USERDEFINED; Material: Tecido de sombreamento — hipótese
Pset_CasaProvenance - DesignSource: Casa Sobreposta / configuration.json; ReferenceFile: 260617_CasaDFL_Estrutura_Terreno.ifc; ConstructionBasis: DESIGN_ASSUMPTION; Note: Same fabric intent as internal shades, shown partially deployed. No wind-speed rating; retraction does not prove storm safety.

# IfcDoor (22)
PredefinedType: DOOR
Pset_CasaProvenance - DesignSource: Casa Sobreposta / configuration.json; ReferenceFile: 260617_CasaDFL_Estrutura_Terreno.ifc
Name | In | OverallHeight (m) | OverallWidth (m) | OperationType | Material | ConstructionBasis
Porta interior 1 | 00 · Habitação e estacionamento | 2.1 | 0.830093 | SINGLE_SWING_LEFT | OSB | ADAPTED_REFERENCE
Porta interior 2 | 00 · Habitação e estacionamento | 2.1 | 0.830093 | SINGLE_SWING_LEFT | OSB | ADAPTED_REFERENCE
Porta interior 3 | 00 · Habitação e estacionamento | 2.1 | 0.730086 | SINGLE_SWING_LEFT | OSB | ADAPTED_REFERENCE
Porta interior 4 | 00 · Habitação e estacionamento | 2.1 | 0.830092 | SINGLE_SWING_LEFT | OSB | ADAPTED_REFERENCE
Porta interior 5 | 00 · Habitação e estacionamento | 2.1 | 0.830077 | SINGLE_SWING_LEFT | OSB | ADAPTED_REFERENCE
Porta interior 6 | 00 · Habitação e estacionamento | 2.1 | 0.730017 | SINGLE_SWING_LEFT | OSB | ADAPTED_REFERENCE
Porta do estacionamento | 00 · Habitação e estacionamento | 2.1 | 0.83 | SINGLE_SWING_LEFT | Aço pintado / Stahl lackiert | ADAPTED_REFERENCE
Folha de correr sul 2 | 00 · Habitação e estacionamento | 2.918 | 1.97133 | SLIDING_TO_LEFT | Vidro / Normalglas | DESIGN_ASSUMPTION
Folha de correr sul 4 | 00 · Habitação e estacionamento | 2.918 | 1.97133 | SLIDING_TO_LEFT | Vidro / Normalglas | DESIGN_ASSUMPTION
Folha de correr sul 6 | 00 · Habitação e estacionamento | 2.918 | 1.97133 | SLIDING_TO_LEFT | Vidro / Normalglas | DESIGN_ASSUMPTION
Folha de correr sul 8 | 00 · Habitação e estacionamento | 2.918 | 1.97133 | SLIDING_TO_LEFT | Vidro / Normalglas | DESIGN_ASSUMPTION
Folha de correr sul 10 | 00 · Habitação e estacionamento | 2.918 | 1.97133 | SLIDING_TO_LEFT | Vidro / Normalglas | DESIGN_ASSUMPTION
Folha de correr sul 12 | 00 · Habitação e estacionamento | 2.918 | 0.614 | SLIDING_TO_LEFT | Vidro / Normalglas | DESIGN_ASSUMPTION
Fachada poente integralmente envidraçada · módulo 4 | 00 · Habitação e estacionamento | 2.918 | 1.55 | SLIDING_TO_LEFT | Vidro / Normalglas | DESIGN_ASSUMPTION | Pset_CasaGlazedFacade - Revision: R02 · kiwi pergola; Facade: WEST / highlighted end in user sketch; Infill: Full-height glazing; no opaque infill; GlazingSpecification: 8 mm nominal representation only; insulated safety glazing assembly to specify
Porta banho superior | 01 · Jardim de inverno | 2.1 | 0.8 | SINGLE_SWING_LEFT | OSB | ADAPTED_REFERENCE
Varanda · porta de correr oeste | 01 · Jardim de inverno | 2.15 | 1.05 | SLIDING_TO_LEFT | Vidro / Normalglas | DESIGN_ASSUMPTION
Caixa térmica 1 · north | 01 · Jardim de inverno | 2.15 | 0.9 | SLIDING_TO_LEFT | Vidro / Normalglas | DESIGN_ASSUMPTION
Caixa térmica 2 · south | 01 · Jardim de inverno | 2.15 | 0.91 | SLIDING_TO_LEFT | Vidro / Normalglas | DESIGN_ASSUMPTION
2 x Contentor · porta dupla | 00 · Habitação e estacionamento | 2.39 | 1.17 | SINGLE_SWING_LEFT | Contentor · pintura 1 | DESIGN_ASSUMPTION
2 x Contentor · porta dupla | 00 · Habitação e estacionamento | 2.39 | 1.17 | SINGLE_SWING_LEFT | Contentor · pintura 2 | DESIGN_ASSUMPTION

# IfcElementAssembly: CISTERN_PODIUM, Pódio · terraço, casa térrea e cisterna
In: 00 · Habitação e estacionamento
PredefinedType: USERDEFINED
Pset_CasaProvenance - DesignSource: Casa Sobreposta / configuration.json; ReferenceFile: 260617_CasaDFL_Estrutura_Terreno.ifc; ConstructionBasis: DESIGN_ASSUMPTION
Pset_CasaUndercroft - NaturalGroundRetained: no; EnclosedStorage: no; Use: Open ventilated sloping void; not a habitable or storage storey; StructuralStatus: Concept slab, beams, piers and foundation sizes; geotechnical and structural design pending
Pset_CasaPodium - TankGrossPlan_m2: 23; TankBaseLevel_m: 12.05; MinimumInternalHeight_m: 2.31; FloorSupport: Hybrid podium: west spans retained slope; local formation east; parking supported by soil; PlanningAssumption: Cistern excluded from 250 m2 by explicit user confirmation 2026-10-02

# IfcElementAssembly: EXISTING_SHIPPING_CONTAINER (2)
In: 00 · Habitação e estacionamento
PredefinedType: USERDEFINED
Pset_CasaProvenance - DesignSource: Casa Sobreposta / configuration.json; ReferenceFile: 260617_CasaDFL_Estrutura_Terreno.ifc; ConstructionBasis: DESIGN_ASSUMPTION
Pset_CasaExistingContext - Length_m: 6; WidthAssumed_m: 2.44; HeightAssumed_m: 2.59; Location: Digitised visible roofs from signed orthophoto; fitted 6 x 2.44 m, provisional +/- 0.50 m, verify ground corners; Status: Existing context; not included in new building setback or new floor-area schedule; Colour: Illustrative, condition not surveyed
Name
Contentor existente 1 · 6 m
Contentor existente 2 · 6 m

# IfcElementAssembly: LIVING_SHADE_TRELLIS, Fachada sul e pátio · estrutura e trepadeiras
In: 00 · Habitação e estacionamento
PredefinedType: USERDEFINED
Pset_CasaProvenance - DesignSource: Casa Sobreposta / configuration.json; ReferenceFile: 260617_CasaDFL_Estrutura_Terreno.ifc; ConstructionBasis: DESIGN_ASSUMPTION

# IfcElementAssembly: PERGOLA_GREENHOUSE_EXTENSION, Pérgola · prolongamento da estufa 6 m
In: 00 · Habitação e estacionamento
PredefinedType: USERDEFINED
Pset_CasaProvenance - DesignSource: Casa Sobreposta / configuration.json; ReferenceFile: 260617_CasaDFL_Estrutura_Terreno.ifc; ConstructionBasis: DESIGN_ASSUMPTION
Pset_CasaVeranda - ClearWidth_m: 1.2; GrossArea_m2: 9.875; PlanningStatus: Counted conservatively in 250 m2 budget; municipal classification unconfirmed
Pset_CasaPergola - Projection_m: 6; Frontage_m: 7.9; OpenCanopyArea_m2: 47.4; EavesRelativeHeight_m: 6.22; Roof: Open extension of greenhouse curved profile, no glass enclosure; StructuralStatus: Gravity and lateral load path indicated; no wind-speed rating or member/anchor verification

# IfcFooting (56)
Material: Betão armado / Stahlbeton
Pset_CasaProvenance - DesignSource: Casa Sobreposta / configuration.json; ReferenceFile: 260617_CasaDFL_Estrutura_Terreno.ifc
Name | In | PredefinedType | ConstructionBasis
Sapata 1A · hipótese | 00 · Habitação e estacionamento | PAD_FOOTING | ADAPTED_REFERENCE | Pset_CasaProvenance - Note: 1.20 x 1.20 x 0.35 m assumed pad; R03 steps below original ground where survey is available. Bearing, settlement and reinforcement unverified.
Sapata 1B · hipótese | 00 · Habitação e estacionamento | PAD_FOOTING | ADAPTED_REFERENCE | Pset_CasaProvenance - Note: 1.20 x 1.20 x 0.35 m assumed pad; R03 steps below original ground where survey is available. Bearing, settlement and reinforcement unverified.
Sapata 2A · hipótese | 00 · Habitação e estacionamento | PAD_FOOTING | ADAPTED_REFERENCE | Pset_CasaProvenance - Note: 1.20 x 1.20 x 0.35 m assumed pad; R03 steps below original ground where survey is available. Bearing, settlement and reinforcement unverified.
Sapata 2B · hipótese | 00 · Habitação e estacionamento | PAD_FOOTING | ADAPTED_REFERENCE | Pset_CasaProvenance - Note: 1.20 x 1.20 x 0.35 m assumed pad; R03 steps below original ground where survey is available. Bearing, settlement and reinforcement unverified.
Sapata 3A · hipótese | 00 · Habitação e estacionamento | PAD_FOOTING | ADAPTED_REFERENCE | Pset_CasaProvenance - Note: 1.20 x 1.20 x 0.35 m assumed pad; R03 steps below original ground where survey is available. Bearing, settlement and reinforcement unverified.
Sapata 3B · hipótese | 00 · Habitação e estacionamento | PAD_FOOTING | ADAPTED_REFERENCE | Pset_CasaProvenance - Note: 1.20 x 1.20 x 0.35 m assumed pad; R03 steps below original ground where survey is available. Bearing, settlement and reinforcement unverified.
Sapata 4A · hipótese | 00 · Habitação e estacionamento | PAD_FOOTING | ADAPTED_REFERENCE | Pset_CasaProvenance - Note: 1.20 x 1.20 x 0.35 m assumed pad; R03 steps below original ground where survey is available. Bearing, settlement and reinforcement unverified.
Sapata 4B · hipótese | 00 · Habitação e estacionamento | PAD_FOOTING | ADAPTED_REFERENCE | Pset_CasaProvenance - Note: 1.20 x 1.20 x 0.35 m assumed pad; R03 steps below original ground where survey is available. Bearing, settlement and reinforcement unverified.
Sapata 5A · hipótese | 00 · Habitação e estacionamento | PAD_FOOTING | ADAPTED_REFERENCE | Pset_CasaProvenance - Note: 1.20 x 1.20 x 0.35 m assumed pad; R03 steps below original ground where survey is available. Bearing, settlement and reinforcement unverified.
Sapata 5B · hipótese | 00 · Habitação e estacionamento | PAD_FOOTING | ADAPTED_REFERENCE | Pset_CasaProvenance - Note: 1.20 x 1.20 x 0.35 m assumed pad; R03 steps below original ground where survey is available. Bearing, settlement and reinforcement unverified.
Sapata 6A · hipótese | 00 · Habitação e estacionamento | PAD_FOOTING | ADAPTED_REFERENCE | Pset_CasaProvenance - Note: 1.20 x 1.20 x 0.35 m assumed pad; R03 steps below original ground where survey is available. Bearing, settlement and reinforcement unverified.
Sapata 6B · hipótese | 00 · Habitação e estacionamento | PAD_FOOTING | ADAPTED_REFERENCE | Pset_CasaProvenance - Note: 1.20 x 1.20 x 0.35 m assumed pad; R03 steps below original ground where survey is available. Bearing, settlement and reinforcement unverified.
Sapata 7A · hipótese | 00 · Habitação e estacionamento | PAD_FOOTING | ADAPTED_REFERENCE | Pset_CasaProvenance - Note: 1.20 x 1.20 x 0.35 m assumed pad; R03 steps below original ground where survey is available. Bearing, settlement and reinforcement unverified.
Sapata 7B · hipótese | 00 · Habitação e estacionamento | PAD_FOOTING | ADAPTED_REFERENCE | Pset_CasaProvenance - Note: 1.20 x 1.20 x 0.35 m assumed pad; R03 steps below original ground where survey is available. Bearing, settlement and reinforcement unverified.
Sapata 8A · hipótese | 00 · Habitação e estacionamento | PAD_FOOTING | ADAPTED_REFERENCE | Pset_CasaProvenance - Note: 1.20 x 1.20 x 0.35 m assumed pad; R03 steps below original ground where survey is available. Bearing, settlement and reinforcement unverified.
Sapata 8B · hipótese | 00 · Habitação e estacionamento | PAD_FOOTING | ADAPTED_REFERENCE | Pset_CasaProvenance - Note: 1.20 x 1.20 x 0.35 m assumed pad; R03 steps below original ground where survey is available. Bearing, settlement and reinforcement unverified.
Cisterna · sapata corrida poente | -01 · Cisterna sob o terraço | STRIP_FOOTING | DESIGN_ASSUMPTION
Cisterna · sapata corrida norte | -01 · Cisterna sob o terraço | STRIP_FOOTING | DESIGN_ASSUMPTION
Cisterna · sapata corrida sul | -01 · Cisterna sob o terraço | STRIP_FOOTING | DESIGN_ASSUMPTION
Cisterna · sapata corrida nascente | -01 · Cisterna sob o terraço | STRIP_FOOTING | DESIGN_ASSUMPTION
4 x Jardim · apoio | 00 · Habitação e estacionamento | PAD_FOOTING | DESIGN_ASSUMPTION
24 x Pódio suspenso · sapata pontual | 00 · Habitação e estacionamento | PAD_FOOTING | DESIGN_ASSUMPTION
8 x Contentor · bloco de apoio nivelado | 00 · Habitação e estacionamento | PAD_FOOTING | DESIGN_ASSUMPTION

# IfcFurnishingElement, Ilha da cozinha · esquema
In: 00 · Habitação e estacionamento
Material: OSB
Pset_CasaProvenance - DesignSource: Casa Sobreposta / configuration.json; ReferenceFile: 260617_CasaDFL_Estrutura_Terreno.ifc; ConstructionBasis: ADAPTED_REFERENCE

# IfcGeographicElement, Terreno · R09 com telha, cisterna e drenagem
In: Lares · Rua das Mercês · artigo 4771
PredefinedType: TERRAIN; Material: Terreno · modelação proposta
Pset_CasaProvenance - DesignSource: Casa Sobreposta / configuration.json; ReferenceFile: 260617_CasaDFL_Estrutura_Terreno.ifc; ConstructionBasis: DESIGN_ASSUMPTION

# IfcGeographicElement: ANALYTICAL_CUT_VOLUME, Escavação · diferença entre terrenos
In: Lares · Rua das Mercês · artigo 4771
PredefinedType: USERDEFINED; Material: Escavação · volume analítico
Pset_CasaProvenance - DesignSource: Casa Sobreposta / configuration.json; ReferenceFile: 260617_CasaDFL_Estrutura_Terreno.ifc; ConstructionBasis: DESIGN_ASSUMPTION; Note: ANALYTICAL VOLUME, not additional constructed material. Closed wedges between surveyed and proposed TIN, split where sign changes. Excludes stripping, foundations, services and bulking.
Pset_CasaEarthworks - Kind: CUT; Volume_m3: 96.4024; Method: Exact signed integration of linear proposed/existing display TIN, splitting zero crossings; Excluded: Topsoil stripping, foundation/service trenches, soil replacement, bulking and shrinkage; Status: CONCEPT_GEOMETRIC_VOLUME; not a measured bill of works; DefaultVisibility: Hide analytical volumes in normal model views
Qto_CasaEarthworks - NetVolume: 96.4024 m3

# IfcGeographicElement: ANALYTICAL_FILL_VOLUME, Aterro · diferença entre terrenos
In: Lares · Rua das Mercês · artigo 4771
PredefinedType: USERDEFINED; Material: Aterro · volume analítico
Pset_CasaProvenance - DesignSource: Casa Sobreposta / configuration.json; ReferenceFile: 260617_CasaDFL_Estrutura_Terreno.ifc; ConstructionBasis: DESIGN_ASSUMPTION; Note: ANALYTICAL VOLUME, not additional constructed material. Closed wedges between surveyed and proposed TIN, split where sign changes. Excludes stripping, foundations, services and bulking.
Pset_CasaEarthworks - Kind: FILL; Volume_m3: 5.19635; Method: Exact signed integration of linear proposed/existing display TIN, splitting zero crossings; Excluded: Topsoil stripping, foundation/service trenches, soil replacement, bulking and shrinkage; Status: CONCEPT_GEOMETRIC_VOLUME; not a measured bill of works; DefaultVisibility: Hide analytical volumes in normal model views
Qto_CasaEarthworks - NetVolume: 5.19635 m3

# IfcGeographicElement: Acesso trapezoidal · 8,60 m no pódio / 5,00 m na rua
In: Lares · Rua das Mercês · artigo 4771
PredefinedType: USERDEFINED; Material: Pavimento rugoso · betão vassourado
Pset_CasaProvenance - DesignSource: Casa Sobreposta / configuration.json; ReferenceFile: 260617_CasaDFL_Estrutura_Terreno.ifc; ConstructionBasis: DESIGN_ASSUMPTION

# IfcGeographicElement: Marcação no solo · árvore indicativa 01
In: Lares · Rua das Mercês · artigo 4771
PredefinedType: USERDEFINED; Material: Marcação de plantação · linha no terreno
Pset_CasaProvenance - DesignSource: Casa Sobreposta / configuration.json; ReferenceFile: 260617_CasaDFL_Estrutura_Terreno.ifc; ConstructionBasis: DESIGN_ASSUMPTION; Note: R09 concept geometry; dimensions and connections not structurally verified.
Pset_PlantingReserve - Diameter_m: 3; Representation: GROUND_CIRCLE_ONLY; Species: UNSPECIFIED; Status: Indicative position and spacing, not a mature canopy guarantee

# IfcGeographicElement: Marcação no solo · árvore indicativa 02
In: Lares · Rua das Mercês · artigo 4771
PredefinedType: USERDEFINED; Material: Marcação de plantação · linha no terreno
Pset_CasaProvenance - DesignSource: Casa Sobreposta / configuration.json; ReferenceFile: 260617_CasaDFL_Estrutura_Terreno.ifc; ConstructionBasis: DESIGN_ASSUMPTION; Note: R09 concept geometry; dimensions and connections not structurally verified.
Pset_PlantingReserve - Diameter_m: 3; Representation: GROUND_CIRCLE_ONLY; Species: UNSPECIFIED; Status: Indicative position and spacing, not a mature canopy guarantee

# IfcGeographicElement: Marcação no solo · árvore indicativa 03
In: Lares · Rua das Mercês · artigo 4771
PredefinedType: USERDEFINED; Material: Marcação de plantação · linha no terreno
Pset_CasaProvenance - DesignSource: Casa Sobreposta / configuration.json; ReferenceFile: 260617_CasaDFL_Estrutura_Terreno.ifc; ConstructionBasis: DESIGN_ASSUMPTION; Note: R09 concept geometry; dimensions and connections not structurally verified.
Pset_PlantingReserve - Diameter_m: 3; Representation: GROUND_CIRCLE_ONLY; Species: UNSPECIFIED; Status: Indicative position and spacing, not a mature canopy guarantee

# IfcGeographicElement: Marcação no solo · árvore indicativa 04
In: Lares · Rua das Mercês · artigo 4771
PredefinedType: USERDEFINED; Material: Marcação de plantação · linha no terreno
Pset_CasaProvenance - DesignSource: Casa Sobreposta / configuration.json; ReferenceFile: 260617_CasaDFL_Estrutura_Terreno.ifc; ConstructionBasis: DESIGN_ASSUMPTION; Note: R09 concept geometry; dimensions and connections not structurally verified.
Pset_PlantingReserve - Diameter_m: 3; Representation: GROUND_CIRCLE_ONLY; Species: UNSPECIFIED; Status: Indicative position and spacing, not a mature canopy guarantee

# IfcGeographicElement: Marcação no solo · árvore indicativa 05
In: Lares · Rua das Mercês · artigo 4771
PredefinedType: USERDEFINED; Material: Marcação de plantação · linha no terreno
Pset_CasaProvenance - DesignSource: Casa Sobreposta / configuration.json; ReferenceFile: 260617_CasaDFL_Estrutura_Terreno.ifc; ConstructionBasis: DESIGN_ASSUMPTION; Note: R09 concept geometry; dimensions and connections not structurally verified.
Pset_PlantingReserve - Diameter_m: 3; Representation: GROUND_CIRCLE_ONLY; Species: UNSPECIFIED; Status: Indicative position and spacing, not a mature canopy guarantee

# IfcGeographicElement: Marcação no solo · árvore indicativa 06
In: Lares · Rua das Mercês · artigo 4771
PredefinedType: USERDEFINED; Material: Marcação de plantação · linha no terreno
Pset_CasaProvenance - DesignSource: Casa Sobreposta / configuration.json; ReferenceFile: 260617_CasaDFL_Estrutura_Terreno.ifc; ConstructionBasis: DESIGN_ASSUMPTION; Note: R09 concept geometry; dimensions and connections not structurally verified.
Pset_PlantingReserve - Diameter_m: 3; Representation: GROUND_CIRCLE_ONLY; Species: UNSPECIFIED; Status: Indicative position and spacing, not a mature canopy guarantee

# IfcGeographicElement: Marcação no solo · árvore indicativa 07
In: Lares · Rua das Mercês · artigo 4771
PredefinedType: USERDEFINED; Material: Marcação de plantação · linha no terreno
Pset_CasaProvenance - DesignSource: Casa Sobreposta / configuration.json; ReferenceFile: 260617_CasaDFL_Estrutura_Terreno.ifc; ConstructionBasis: DESIGN_ASSUMPTION; Note: R09 concept geometry; dimensions and connections not structurally verified.
Pset_PlantingReserve - Diameter_m: 3; Representation: GROUND_CIRCLE_ONLY; Species: UNSPECIFIED; Status: Indicative position and spacing, not a mature canopy guarantee

# IfcGeographicElement: Marcação no solo · árvore indicativa 08
In: Lares · Rua das Mercês · artigo 4771
PredefinedType: USERDEFINED; Material: Marcação de plantação · linha no terreno
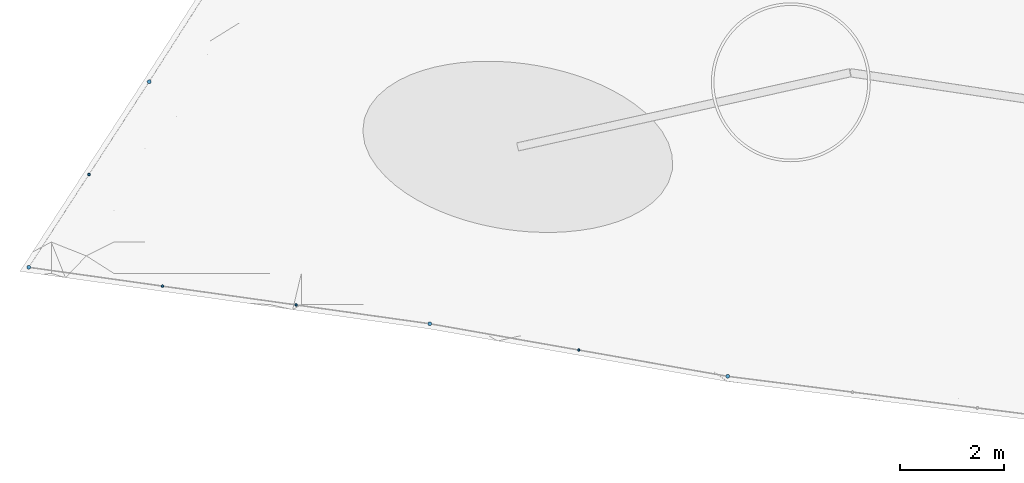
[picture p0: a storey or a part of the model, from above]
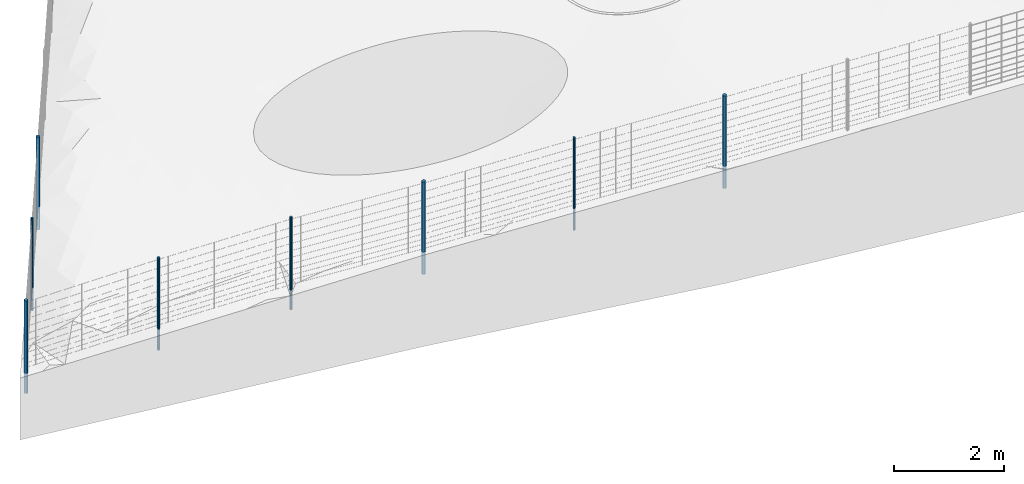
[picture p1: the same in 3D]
Properties of the parts of a building model (IFC4), part 2 of 3

# IfcGeographicElement: Marcação no solo · árvore indicativa 08
Pset_CasaProvenance - DesignSource: Casa Sobreposta / configuration.json; ReferenceFile: 260617_CasaDFL_Estrutura_Terreno.ifc; ConstructionBasis: DESIGN_ASSUMPTION; Note: R09 concept geometry; dimensions and connections not structurally verified.
Pset_PlantingReserve - Diameter_m: 3; Representation: GROUND_CIRCLE_ONLY; Species: UNSPECIFIED; Status: Indicative position and spacing, not a mature canopy guarantee

# IfcGeographicElement: Marcação no solo · árvore indicativa 09
In: Lares · Rua das Mercês · artigo 4771
PredefinedType: USERDEFINED; Material: Marcação de plantação · linha no terreno
Pset_CasaProvenance - DesignSource: Casa Sobreposta / configuration.json; ReferenceFile: 260617_CasaDFL_Estrutura_Terreno.ifc; ConstructionBasis: DESIGN_ASSUMPTION; Note: R09 concept geometry; dimensions and connections not structurally verified.
Pset_PlantingReserve - Diameter_m: 3; Representation: GROUND_CIRCLE_ONLY; Species: UNSPECIFIED; Status: Indicative position and spacing, not a mature canopy guarantee

# IfcGeographicElement: Marcação no solo · árvore indicativa 10
In: Lares · Rua das Mercês · artigo 4771
PredefinedType: USERDEFINED; Material: Marcação de plantação · linha no terreno
Pset_CasaProvenance - DesignSource: Casa Sobreposta / configuration.json; ReferenceFile: 260617_CasaDFL_Estrutura_Terreno.ifc; ConstructionBasis: DESIGN_ASSUMPTION; Note: R09 concept geometry; dimensions and connections not structurally verified.
Pset_PlantingReserve - Diameter_m: 3; Representation: GROUND_CIRCLE_ONLY; Species: UNSPECIFIED; Status: Indicative position and spacing, not a mature canopy guarantee

# IfcGeographicElement: VEGETATION, Trepadeiras · folhas individuais, estado ilustrativo
In: 00 · Habitação e estacionamento
PredefinedType: USERDEFINED; Material: Folhagem · trepadeiras
Pset_CasaProvenance - DesignSource: Casa Sobreposta / configuration.json; ReferenceFile: 260617_CasaDFL_Estrutura_Terreno.ifc; ConstructionBasis: DESIGN_ASSUMPTION; Note: Procedural leaves for visual intent only; no predicted growth, species performance or wind protection.

# IfcMember (154)
In: 00 · Habitação e estacionamento
Pset_CasaProvenance - DesignSource: Casa Sobreposta / configuration.json; ReferenceFile: 260617_CasaDFL_Estrutura_Terreno.ifc; ConstructionBasis: DESIGN_ASSUMPTION
Name | Material
4 x Contentor · canto | Contentor · pintura 1
50 x Contentor · nervura lateral | Contentor · pintura 1
23 x Contentor · nervura cobertura | Contentor · pintura 1
4 x Contentor · canto | Contentor · pintura 2
50 x Contentor · nervura lateral | Contentor · pintura 2
23 x Contentor · nervura cobertura | Contentor · pintura 2

# IfcMember: C240 / steel (6)
In: 00 · Habitação e estacionamento
Type - Material: Aço pintado / Stahl lackiert
Pset_CasaProvenance - DesignSource: Casa Sobreposta / configuration.json; ReferenceFile: 260617_CasaDFL_Estrutura_Terreno.ifc; ConstructionBasis: ADAPTED_REFERENCE; Note: Reference section; spans, stability and connections require design.
Name
2 x Longarina metálica sala
2 x Longarina metálica garagem
2 x Jardim · longarina poente

# IfcMember: D0.004 / galvanized (257)
In: 00 · Habitação e estacionamento
Type - Material: Aço galvanizado / Stahl verzinkt
Pset_CasaProvenance - DesignSource: Casa Sobreposta / configuration.json; ReferenceFile: 260617_CasaDFL_Estrutura_Terreno.ifc; ConstructionBasis: DESIGN_ASSUMPTION; Note: Reference section; spans, stability and connections require design.
Name
120 x Pérgola · fio para trepadeiras
70 x Trepadeiras · fio horizontal
67 x Trepadeiras · fio vertical

# IfcMember: D0.015 / vine_wood (627)
In: 00 · Habitação e estacionamento
Type - Material: Ramos de trepadeiras
Pset_CasaProvenance - DesignSource: Casa Sobreposta / configuration.json; ReferenceFile: 260617_CasaDFL_Estrutura_Terreno.ifc; ConstructionBasis: DESIGN_ASSUMPTION; Note: Reference section; spans, stability and connections require design.

# IfcMember: D0.016 / steel (2)
In: 00 · Habitação e estacionamento
Type - Material: Aço pintado / Stahl lackiert
Pset_CasaProvenance - DesignSource: Casa Sobreposta / configuration.json; ReferenceFile: 260617_CasaDFL_Estrutura_Terreno.ifc; ConstructionBasis: DESIGN_ASSUMPTION; Note: Reference section; spans, stability and connections require design.

# IfcMember: D0.025 / galvanized (8)
In: 00 · Habitação e estacionamento
Type - Material: Aço galvanizado / Stahl verzinkt
Pset_CasaProvenance - DesignSource: Casa Sobreposta / configuration.json; ReferenceFile: 260617_CasaDFL_Estrutura_Terreno.ifc; ConstructionBasis: DESIGN_ASSUMPTION; Note: Reference section; spans, stability and connections require design.

# IfcMember: D0.048 / galvanized (57)
In: Lares · Rua das Mercês · artigo 4771
Type - Material: Aço galvanizado / Stahl verzinkt
PredefinedType: POST
Pset_CasaProvenance - DesignSource: Casa Sobreposta / configuration.json; ReferenceFile: 260617_CasaDFL_Estrutura_Terreno.ifc; ConstructionBasis: DESIGN_ASSUMPTION; Note: Galvanised steel tube post, nominal; embedment, concrete base and strainer bracing to detail.

# IfcMember: D0.076 / galvanized (26)
In: Lares · Rua das Mercês · artigo 4771
Type - Material: Aço galvanizado / Stahl verzinkt
PredefinedType: POST
Pset_CasaProvenance - DesignSource: Casa Sobreposta / configuration.json; ReferenceFile: 260617_CasaDFL_Estrutura_Terreno.ifc; ConstructionBasis: DESIGN_ASSUMPTION; Note: Galvanised steel tube post, nominal; embedment, concrete base and strainer bracing to detail.

# IfcMember: R0.018 / galvanized (557)
In: Lares · Rua das Mercês · artigo 4771
Type - Material: Aço galvanizado / Stahl verzinkt
Pset_CasaProvenance - DesignSource: Casa Sobreposta / configuration.json; ReferenceFile: 260617_CasaDFL_Estrutura_Terreno.ifc; ConstructionBasis: DESIGN_ASSUMPTION; Note: Reference section; spans, stability and connections require design.
Name
469 x Acesso · dreno lateral raso · grelha
32 x Interceção · caleira rua · grelha
56 x Interceção · caleira estacionamento · grelha

# IfcMember: R0.035 / steel (557)
Type - Material: Aço pintado / Stahl lackiert
Pset_CasaProvenance - DesignSource: Casa Sobreposta / configuration.json; ReferenceFile: 260617_CasaDFL_Estrutura_Terreno.ifc; ConstructionBasis: ADAPTED_REFERENCE; Note: Reference section; spans, stability and connections require design.
Name | In
2 x Rasgo norte 1 · montante | 00 · Habitação e estacionamento
2 x Rasgo norte 1 · travessa | 00 · Habitação e estacionamento
2 x Rasgo norte 2 · montante | 00 · Habitação e estacionamento
2 x Rasgo norte 2 · travessa | 00 · Habitação e estacionamento
2 x Rasgo norte 3 · montante | 00 · Habitação e estacionamento
2 x Rasgo norte 3 · travessa | 00 · Habitação e estacionamento
2 x Rasgo norte 4 · montante | 00 · Habitação e estacionamento
2 x Rasgo norte 4 · travessa | 00 · Habitação e estacionamento
2 x Rasgo norte 5 · montante | 00 · Habitação e estacionamento
2 x Rasgo norte 5 · travessa | 00 · Habitação e estacionamento
2 x Rasgo norte 6 · montante | 00 · Habitação e estacionamento
2 x Rasgo norte 6 · travessa | 00 · Habitação e estacionamento
2 x Rasgo norte 7 · montante | 00 · Habitação e estacionamento
2 x Rasgo norte 7 · travessa | 00 · Habitação e estacionamento
2 x Folha de correr sul 2 · montante | 00 · Habitação e estacionamento
2 x Folha de correr sul 2 · travessa | 00 · Habitação e estacionamento
2 x Folha de correr sul 4 · montante | 00 · Habitação e estacionamento
2 x Folha de correr sul 4 · travessa | 00 · Habitação e estacionamento
2 x Folha de correr sul 6 · montante | 00 · Habitação e estacionamento
2 x Folha de correr sul 6 · travessa | 00 · Habitação e estacionamento
2 x Folha de correr sul 8 · montante | 00 · Habitação e estacionamento
2 x Folha de correr sul 8 · travessa | 00 · Habitação e estacionamento
2 x Folha de correr sul 10 · montante | 00 · Habitação e estacionamento
2 x Folha de correr sul 10 · travessa | 00 · Habitação e estacionamento
2 x Folha de correr sul 12 · montante | 00 · Habitação e estacionamento
2 x Folha de correr sul 12 · travessa | 00 · Habitação e estacionamento
2 x Fachada poente integralmente envidraçada · módulo 1 · montante | 00 · Habitação e estacionamento
2 x Fachada poente integralmente envidraçada · módulo 1 · travessa | 00 · Habitação e estacionamento
2 x Fachada poente integralmente envidraçada · módulo 2 · montante | 00 · Habitação e estacionamento
2 x Fachada poente integralmente envidraçada · módulo 2 · travessa | 00 · Habitação e estacionamento
2 x Fachada poente integralmente envidraçada · módulo 3 · montante | 00 · Habitação e estacionamento
2 x Fachada poente integralmente envidraçada · módulo 3 · travessa | 00 · Habitação e estacionamento
2 x Fachada poente integralmente envidraçada · módulo 4 · montante | 00 · Habitação e estacionamento
2 x Fachada poente integralmente envidraçada · módulo 4 · travessa | 00 · Habitação e estacionamento
2 x Estufa sul 1 · montante | 01 · Jardim de inverno
2 x Estufa sul 1 · travessa | 01 · Jardim de inverno
4 x Entrada de ar sul 1 | 01 · Jardim de inverno
2 x Estufa sul 2 · montante | 01 · Jardim de inverno
2 x Estufa sul 2 · travessa | 01 · Jardim de inverno
4 x Entrada de ar sul 2 | 01 · Jardim de inverno
2 x Estufa sul 3 · montante | 01 · Jardim de inverno
2 x Estufa sul 3 · travessa | 01 · Jardim de inverno
4 x Entrada de ar sul 3 | 01 · Jardim de inverno
2 x Estufa sul 4 · montante | 01 · Jardim de inverno
2 x Estufa sul 4 · travessa | 01 · Jardim de inverno
4 x Entrada de ar sul 4 | 01 · Jardim de inverno
2 x Estufa sul 5 · montante | 01 · Jardim de inverno
2 x Estufa sul 5 · travessa | 01 · Jardim de inverno
4 x Entrada de ar sul 5 | 01 · Jardim de inverno
2 x Estufa sul 6 · montante | 01 · Jardim de inverno
2 x Estufa sul 6 · travessa | 01 · Jardim de inverno
4 x Entrada de ar sul 6 | 01 · Jardim de inverno
2 x Estufa sul 7 · montante | 01 · Jardim de inverno
2 x Estufa sul 7 · travessa | 01 · Jardim de inverno
4 x Entrada de ar sul 7 | 01 · Jardim de inverno
2 x Estufa sul 8 · montante | 01 · Jardim de inverno
2 x Estufa sul 8 · travessa | 01 · Jardim de inverno
4 x Entrada de ar sul 8 | 01 · Jardim de inverno
2 x Estufa sul 9 · montante | 01 · Jardim de inverno
2 x Estufa sul 9 · travessa | 01 · Jardim de inverno
4 x Entrada de ar sul 9 | 01 · Jardim de inverno
2 x Estufa sul 10 · montante | 01 · Jardim de inverno
2 x Estufa sul 10 · travessa | 01 · Jardim de inverno
4 x Entrada de ar sul 10 | 01 · Jardim de inverno
2 x Estufa sul 11 · montante | 01 · Jardim de inverno
2 x Estufa sul 11 · travessa | 01 · Jardim de inverno
4 x Entrada de ar sul 11 | 01 · Jardim de inverno
2 x Estufa sul 12 · montante | 01 · Jardim de inverno
2 x Estufa sul 12 · travessa | 01 · Jardim de inverno
4 x Entrada de ar sul 12 | 01 · Jardim de inverno
2 x Estufa sul 13 · montante | 01 · Jardim de inverno
2 x Estufa sul 13 · travessa | 01 · Jardim de inverno
4 x Entrada de ar sul 13 | 01 · Jardim de inverno
2 x Estufa sul 14 · montante | 01 · Jardim de inverno
2 x Estufa sul 14 · travessa | 01 · Jardim de inverno
4 x Entrada de ar sul 14 | 01 · Jardim de inverno
2 x Estufa sul 15 · montante | 01 · Jardim de inverno
2 x Estufa sul 15 · travessa | 01 · Jardim de inverno
4 x Entrada de ar sul 15 | 01 · Jardim de inverno
2 x Estufa sul 16 · montante | 01 · Jardim de inverno
2 x Estufa sul 16 · travessa | 01 · Jardim de inverno
4 x Entrada de ar sul 16 | 01 · Jardim de inverno
2 x Estufa norte 1 · montante | 01 · Jardim de inverno
2 x Estufa norte 1 · travessa | 01 · Jardim de inverno
4 x Entrada de ar norte 1 | 01 · Jardim de inverno
2 x Estufa norte 2 · montante | 01 · Jardim de inverno
2 x Estufa norte 2 · travessa | 01 · Jardim de inverno
4 x Entrada de ar norte 2 | 01 · Jardim de inverno
2 x Estufa norte 3 · montante | 01 · Jardim de inverno
2 x Estufa norte 3 · travessa | 01 · Jardim de inverno
4 x Entrada de ar norte 3 | 01 · Jardim de inverno
2 x Estufa norte 4 · montante | 01 · Jardim de inverno
2 x Estufa norte 4 · travessa | 01 · Jardim de inverno
4 x Entrada de ar norte 4 | 01 · Jardim de inverno
2 x Estufa norte 5 · montante | 01 · Jardim de inverno
2 x Estufa norte 5 · travessa | 01 · Jardim de inverno
4 x Entrada de ar norte 5 | 01 · Jardim de inverno
2 x Estufa norte 6 · montante | 01 · Jardim de inverno
2 x Estufa norte 6 · travessa | 01 · Jardim de inverno
4 x Entrada de ar norte 6 | 01 · Jardim de inverno
2 x Estufa norte 7 · montante | 01 · Jardim de inverno
2 x Estufa norte 7 · travessa | 01 · Jardim de inverno
4 x Entrada de ar norte 7 | 01 · Jardim de inverno
2 x Estufa norte 8 · montante | 01 · Jardim de inverno
2 x Estufa norte 8 · travessa | 01 · Jardim de inverno
4 x Entrada de ar norte 8 | 01 · Jardim de inverno
2 x Estufa norte 9 · montante | 01 · Jardim de inverno
2 x Estufa norte 9 · travessa | 01 · Jardim de inverno
4 x Entrada de ar norte 9 | 01 · Jardim de inverno
2 x Estufa norte 10 · montante | 01 · Jardim de inverno
2 x Estufa norte 10 · travessa | 01 · Jardim de inverno
4 x Entrada de ar norte 10 | 01 · Jardim de inverno
2 x Estufa norte 11 · montante | 01 · Jardim de inverno
2 x Estufa norte 11 · travessa | 01 · Jardim de inverno
4 x Entrada de ar norte 11 | 01 · Jardim de inverno
2 x Estufa norte 12 · montante | 01 · Jardim de inverno
2 x Estufa norte 12 · travessa | 01 · Jardim de inverno
4 x Entrada de ar norte 12 | 01 · Jardim de inverno
2 x Estufa norte 13 · montante | 01 · Jardim de inverno
2 x Estufa norte 13 · travessa | 01 · Jardim de inverno
4 x Entrada de ar norte 13 | 01 · Jardim de inverno
2 x Estufa norte 14 · montante | 01 · Jardim de inverno
2 x Estufa norte 14 · travessa | 01 · Jardim de inverno
4 x Entrada de ar norte 14 | 01 · Jardim de inverno
2 x Estufa norte 15 · montante | 01 · Jardim de inverno
2 x Estufa norte 15 · travessa | 01 · Jardim de inverno
4 x Entrada de ar norte 15 | 01 · Jardim de inverno
2 x Estufa norte 16 · montante | 01 · Jardim de inverno
2 x Estufa norte 16 · travessa | 01 · Jardim de inverno
4 x Entrada de ar norte 16 | 01 · Jardim de inverno
2 x Varanda · porta de correr oeste · montante | 01 · Jardim de inverno
2 x Varanda · porta de correr oeste · travessa | 01 · Jardim de inverno
2 x Varanda · bandeira da porta · montante | 01 · Jardim de inverno
2 x Varanda · bandeira da porta · travessa | 01 · Jardim de inverno
4 x Varanda · vidro lateral · montante | 01 · Jardim de inverno
4 x Varanda · vidro lateral · travessa | 01 · Jardim de inverno
2 x Estufa poente 2 · montante | 01 · Jardim de inverno
2 x Estufa poente 2 · travessa | 01 · Jardim de inverno
2 x Estufa poente 3 · montante | 01 · Jardim de inverno
2 x Estufa poente 3 · travessa | 01 · Jardim de inverno
2 x Estufa poente 4 · montante | 01 · Jardim de inverno
2 x Estufa poente 4 · travessa | 01 · Jardim de inverno
2 x Estufa nascente 1 · montante | 01 · Jardim de inverno
2 x Estufa nascente 1 · travessa | 01 · Jardim de inverno
2 x Estufa nascente 2 · montante | 01 · Jardim de inverno
2 x Estufa nascente 2 · travessa | 01 · Jardim de inverno
2 x Estufa nascente 3 · montante | 01 · Jardim de inverno
2 x Estufa nascente 3 · travessa | 01 · Jardim de inverno
2 x Estufa nascente 4 · montante | 01 · Jardim de inverno
2 x Estufa nascente 4 · travessa | 01 · Jardim de inverno
Arco estufa 0/0 | 01 · Jardim de inverno
Arco estufa 4/0 | 01 · Jardim de inverno
Arco estufa 8/0 | 01 · Jardim de inverno
Arco estufa 12/0 | 01 · Jardim de inverno
Arco estufa 16/0 | 01 · Jardim de inverno
Arco estufa 20/0 | 01 · Jardim de inverno
Arco estufa 24/0 | 01 · Jardim de inverno
Arco estufa 28/0 | 01 · Jardim de inverno
Arco estufa 32/0 | 01 · Jardim de inverno
Arco estufa 0/1 | 01 · Jardim de inverno
Arco estufa 4/1 | 01 · Jardim de inverno
Arco estufa 8/1 | 01 · Jardim de inverno
Arco estufa 12/1 | 01 · Jardim de inverno
Arco estufa 16/1 | 01 · Jardim de inverno
Arco estufa 20/1 | 01 · Jardim de inverno
Arco estufa 24/1 | 01 · Jardim de inverno
Arco estufa 28/1 | 01 · Jardim de inverno
Arco estufa 32/1 | 01 · Jardim de inverno
Arco estufa 0/2 | 01 · Jardim de inverno
Arco estufa 4/2 | 01 · Jardim de inverno
Arco estufa 8/2 | 01 · Jardim de inverno
Arco estufa 12/2 | 01 · Jardim de inverno
Arco estufa 16/2 | 01 · Jardim de inverno
Arco estufa 20/2 | 01 · Jardim de inverno
Arco estufa 24/2 | 01 · Jardim de inverno
Arco estufa 28/2 | 01 · Jardim de inverno
Arco estufa 32/2 | 01 · Jardim de inverno
Arco estufa 0/3 | 01 · Jardim de inverno
Arco estufa 4/3 | 01 · Jardim de inverno
Arco estufa 8/3 | 01 · Jardim de inverno
Arco estufa 12/3 | 01 · Jardim de inverno
Arco estufa 16/3 | 01 · Jardim de inverno
Arco estufa 20/3 | 01 · Jardim de inverno
Arco estufa 24/3 | 01 · Jardim de inverno
Arco estufa 28/3 | 01 · Jardim de inverno
Arco estufa 32/3 | 01 · Jardim de inverno
Arco estufa 0/4 | 01 · Jardim de inverno
Arco estufa 4/4 | 01 · Jardim de inverno
Arco estufa 8/4 | 01 · Jardim de inverno
Arco estufa 12/4 | 01 · Jardim de inverno
Arco estufa 16/4 | 01 · Jardim de inverno
Arco estufa 20/4 | 01 · Jardim de inverno
Arco estufa 24/4 | 01 · Jardim de inverno
Arco estufa 28/4 | 01 · Jardim de inverno
Arco estufa 32/4 | 01 · Jardim de inverno
Arco estufa 0/5 | 01 · Jardim de inverno
Arco estufa 4/5 | 01 · Jardim de inverno
Arco estufa 8/5 | 01 · Jardim de inverno
Arco estufa 12/5 | 01 · Jardim de inverno
Arco estufa 16/5 | 01 · Jardim de inverno
Arco estufa 20/5 | 01 · Jardim de inverno
Arco estufa 24/5 | 01 · Jardim de inverno
Arco estufa 28/5 | 01 · Jardim de inverno
Arco estufa 32/5 | 01 · Jardim de inverno
Arco estufa 0/6 | 01 · Jardim de inverno
Arco estufa 4/6 | 01 · Jardim de inverno
Arco estufa 8/6 | 01 · Jardim de inverno
Arco estufa 12/6 | 01 · Jardim de inverno
Arco estufa 16/6 | 01 · Jardim de inverno
Arco estufa 20/6 | 01 · Jardim de inverno
Arco estufa 24/6 | 01 · Jardim de inverno
Arco estufa 28/6 | 01 · Jardim de inverno
Arco estufa 32/6 | 01 · Jardim de inverno
Arco estufa 0/7 | 01 · Jardim de inverno
Arco estufa 4/7 | 01 · Jardim de inverno
Arco estufa 8/7 | 01 · Jardim de inverno
Arco estufa 12/7 | 01 · Jardim de inverno
Arco estufa 16/7 | 01 · Jardim de inverno
Arco estufa 20/7 | 01 · Jardim de inverno
Arco estufa 24/7 | 01 · Jardim de inverno
Arco estufa 28/7 | 01 · Jardim de inverno
Arco estufa 32/7 | 01 · Jardim de inverno
Arco estufa 0/8 | 01 · Jardim de inverno
Arco estufa 4/8 | 01 · Jardim de inverno
Arco estufa 8/8 | 01 · Jardim de inverno
Arco estufa 12/8 | 01 · Jardim de inverno
Arco estufa 16/8 | 01 · Jardim de inverno
Arco estufa 20/8 | 01 · Jardim de inverno
Arco estufa 24/8 | 01 · Jardim de inverno
Arco estufa 28/8 | 01 · Jardim de inverno
Arco estufa 32/8 | 01 · Jardim de inverno
Arco estufa 0/9 | 01 · Jardim de inverno
Arco estufa 4/9 | 01 · Jardim de inverno
Arco estufa 8/9 | 01 · Jardim de inverno
Arco estufa 12/9 | 01 · Jardim de inverno
Arco estufa 16/9 | 01 · Jardim de inverno
Arco estufa 20/9 | 01 · Jardim de inverno
Arco estufa 24/9 | 01 · Jardim de inverno
Arco estufa 28/9 | 01 · Jardim de inverno
Arco estufa 32/9 | 01 · Jardim de inverno
Arco estufa 0/10 | 01 · Jardim de inverno
Arco estufa 4/10 | 01 · Jardim de inverno
Arco estufa 8/10 | 01 · Jardim de inverno
Arco estufa 12/10 | 01 · Jardim de inverno
Arco estufa 16/10 | 01 · Jardim de inverno
Arco estufa 20/10 | 01 · Jardim de inverno
Arco estufa 24/10 | 01 · Jardim de inverno
Arco estufa 28/10 | 01 · Jardim de inverno
Arco estufa 32/10 | 01 · Jardim de inverno
Arco estufa 0/11 | 01 · Jardim de inverno
Arco estufa 4/11 | 01 · Jardim de inverno
Arco estufa 8/11 | 01 · Jardim de inverno
Arco estufa 12/11 | 01 · Jardim de inverno
Arco estufa 16/11 | 01 · Jardim de inverno
Arco estufa 20/11 | 01 · Jardim de inverno
Arco estufa 24/11 | 01 · Jardim de inverno
Arco estufa 28/11 | 01 · Jardim de inverno
Arco estufa 32/11 | 01 · Jardim de inverno
Arco estufa 0/12 | 01 · Jardim de inverno
Arco estufa 4/12 | 01 · Jardim de inverno
Arco estufa 8/12 | 01 · Jardim de inverno
Arco estufa 12/12 | 01 · Jardim de inverno
Arco estufa 16/12 | 01 · Jardim de inverno
Arco estufa 20/12 | 01 · Jardim de inverno
Arco estufa 24/12 | 01 · Jardim de inverno
Arco estufa 28/12 | 01 · Jardim de inverno
Arco estufa 32/12 | 01 · Jardim de inverno
Arco estufa 0/13 | 01 · Jardim de inverno
Arco estufa 4/13 | 01 · Jardim de inverno
Arco estufa 8/13 | 01 · Jardim de inverno
Arco estufa 12/13 | 01 · Jardim de inverno
Arco estufa 16/13 | 01 · Jardim de inverno
Arco estufa 20/13 | 01 · Jardim de inverno
Arco estufa 24/13 | 01 · Jardim de inverno
Arco estufa 28/13 | 01 · Jardim de inverno
Arco estufa 32/13 | 01 · Jardim de inverno
Arco estufa 0/14 | 01 · Jardim de inverno
Arco estufa 4/14 | 01 · Jardim de inverno
Arco estufa 8/14 | 01 · Jardim de inverno
Arco estufa 12/14 | 01 · Jardim de inverno
Arco estufa 16/14 | 01 · Jardim de inverno
Arco estufa 20/14 | 01 · Jardim de inverno
Arco estufa 24/14 | 01 · Jardim de inverno
Arco estufa 28/14 | 01 · Jardim de inverno
Arco estufa 32/14 | 01 · Jardim de inverno
Arco estufa 0/15 | 01 · Jardim de inverno
Arco estufa 4/15 | 01 · Jardim de inverno
Arco estufa 8/15 | 01 · Jardim de inverno
Arco estufa 12/15 | 01 · Jardim de inverno
Arco estufa 16/15 | 01 · Jardim de inverno
Arco estufa 20/15 | 01 · Jardim de inverno
Arco estufa 24/15 | 01 · Jardim de inverno
Arco estufa 28/15 | 01 · Jardim de inverno
Arco estufa 32/15 | 01 · Jardim de inverno
Arco estufa 0/16 | 01 · Jardim de inverno
Arco estufa 4/16 | 01 · Jardim de inverno
Arco estufa 8/16 | 01 · Jardim de inverno
Arco estufa 12/16 | 01 · Jardim de inverno
Arco estufa 16/16 | 01 · Jardim de inverno
Arco estufa 20/16 | 01 · Jardim de inverno
Arco estufa 24/16 | 01 · Jardim de inverno
Arco estufa 28/16 | 01 · Jardim de inverno
Arco estufa 32/16 | 01 · Jardim de inverno
4 x Terça da estufa | 01 · Jardim de inverno
2 x Caixa térmica 1 · west · montante | 01 · Jardim de inverno
2 x Caixa térmica 1 · west · travessa | 01 · Jardim de inverno
2 x Caixa térmica 1 · east · montante | 01 · Jardim de inverno
2 x Caixa térmica 1 · east · travessa | 01 · Jardim de inverno
2 x Caixa térmica 1 · south · montante | 01 · Jardim de inverno
2 x Caixa térmica 1 · south · travessa | 01 · Jardim de inverno
2 x Caixa térmica 1 · north · montante | 01 · Jardim de inverno
2 x Caixa térmica 1 · north · travessa | 01 · Jardim de inverno
2 x Caixa térmica 2 · west · montante | 01 · Jardim de inverno
2 x Caixa térmica 2 · west · travessa | 01 · Jardim de inverno
2 x Caixa térmica 2 · east · montante | 01 · Jardim de inverno
2 x Caixa térmica 2 · east · travessa | 01 · Jardim de inverno
2 x Caixa térmica 2 · south · montante | 01 · Jardim de inverno
2 x Caixa térmica 2 · south · travessa | 01 · Jardim de inverno
2 x Caixa térmica 2 · north · montante | 01 · Jardim de inverno
2 x Caixa térmica 2 · north · travessa | 01 · Jardim de inverno

# IfcMember: RHS100x60x4 / steel (51)
In: 00 · Habitação e estacionamento
Type - Material: Aço pintado / Stahl lackiert
Pset_CasaProvenance - DesignSource: Casa Sobreposta / configuration.json; ReferenceFile: 260617_CasaDFL_Estrutura_Terreno.ifc; ConstructionBasis: DESIGN_ASSUMPTION; Note: Reference section; spans, stability and connections require design.

# IfcMember: RHS80x60x4 / steel (4)
In: 00 · Habitação e estacionamento
Type - Material: Aço pintado / Stahl lackiert
Pset_CasaProvenance - DesignSource: Casa Sobreposta / configuration.json; ReferenceFile: 260617_CasaDFL_Estrutura_Terreno.ifc; ConstructionBasis: DESIGN_ASSUMPTION; Note: Reference section; spans, stability and connections require design.

# IfcOpeningElement (27)
PredefinedType: OPENING
Pset_CasaProvenance - DesignSource: Casa Sobreposta / configuration.json; ReferenceFile: 260617_CasaDFL_Estrutura_Terreno.ifc; ConstructionBasis: DESIGN_ASSUMPTION; Note: Real subtractive void
Name | In
Vão de escada 1 · OSB estrutural · 20 mm | 01 · Jardim de inverno
Vão de escada 2 · OSB estrutural · 20 mm | 01 · Jardim de inverno
Vão de escada 1 · Impermeabilização da estufa · hipótese | 01 · Jardim de inverno
Vão de escada 2 · Impermeabilização da estufa · hipótese | 01 · Jardim de inverno
Vão de escada 1 · Proteção do pavimento · hipótese | 01 · Jardim de inverno
Vão de escada 2 · Proteção do pavimento · hipótese | 01 · Jardim de inverno
Vão porta interior 1.1 | 00 · Habitação e estacionamento
Vão porta interior 1.2 | 00 · Habitação e estacionamento
Vão porta interior 2.1 | 00 · Habitação e estacionamento
Vão porta interior 2.2 | 00 · Habitação e estacionamento
Vão porta interior 3.1 | 00 · Habitação e estacionamento
Vão porta interior 3.2 | 00 · Habitação e estacionamento
Vão porta interior 4.1 | 00 · Habitação e estacionamento
Vão porta interior 4.2 | 00 · Habitação e estacionamento
Vão porta interior 5.1 | 00 · Habitação e estacionamento
Vão porta interior 6.1 | 00 · Habitação e estacionamento
Vão porta interior 6.2 | 00 · Habitação e estacionamento
Vão rasgo norte 1 | 00 · Habitação e estacionamento
Vão rasgo norte 2 | 00 · Habitação e estacionamento
Vão rasgo norte 3 | 00 · Habitação e estacionamento
Vão rasgo norte 4 | 00 · Habitação e estacionamento
Vão rasgo norte 5 | 00 · Habitação e estacionamento
Vão rasgo norte 6 | 00 · Habitação e estacionamento
Vão rasgo norte 7 | 00 · Habitação e estacionamento
Vão de acesso do estacionamento | 00 · Habitação e estacionamento
Vão banho superior | 01 · Jardim de inverno
Cisterna · abertura de inspeção | 00 · Habitação e estacionamento

# IfcPipeSegment: D0.16 / drain (4)
In: Lares · Rua das Mercês · artigo 4771
Type - Material: Caleiras · betão
Pset_CasaProvenance - DesignSource: Casa Sobreposta / configuration.json; ReferenceFile: 260617_CasaDFL_Estrutura_Terreno.ifc; ConstructionBasis: DESIGN_ASSUMPTION
Name | Note
Acesso · queda pluvial até coletor | Reference section; spans, stability and connections require design.
3 x Acesso · coletor separado da cisterna | Nominal DN160 spatial route only, not hydraulically sized. Silt/contaminant treatment and outlet/infiltration to design.

# IfcPlate (158)
Pset_CasaProvenance - DesignSource: Casa Sobreposta / configuration.json; ReferenceFile: 260617_CasaDFL_Estrutura_Terreno.ifc; ConstructionBasis: DESIGN_ASSUMPTION
Name | In | PredefinedType | Material | Note
Cobertura 1.1 | 01 · Jardim de inverno | SHEET | Vidro / Normalglas | 8 mm nominal glass; safety glazing and panel subdivision require specification.
Cobertura 2.1 | 01 · Jardim de inverno | SHEET | Vidro / Normalglas | 8 mm nominal glass; safety glazing and panel subdivision require specification.
Cobertura 3.1 | 01 · Jardim de inverno | SHEET | Vidro / Normalglas | 8 mm nominal glass; safety glazing and panel subdivision require specification.
Cobertura 4.1 | 01 · Jardim de inverno | SHEET | Vidro / Normalglas | 8 mm nominal glass; safety glazing and panel subdivision require specification.
Cobertura 5.1 | 01 · Jardim de inverno | SHEET | Vidro / Normalglas | 8 mm nominal glass; safety glazing and panel subdivision require specification.
Cobertura 6.1 | 01 · Jardim de inverno | SHEET | Vidro / Normalglas | 8 mm nominal glass; safety glazing and panel subdivision require specification.
Cobertura 7.1 | 01 · Jardim de inverno | SHEET | Vidro / Normalglas | 8 mm nominal glass; safety glazing and panel subdivision require specification.
Cobertura 8.1 | 01 · Jardim de inverno | SHEET | Vidro / Normalglas | 8 mm nominal glass; safety glazing and panel subdivision require specification.
Cobertura 1.2 | 01 · Jardim de inverno | SHEET | Vidro / Normalglas | 8 mm nominal glass; safety glazing and panel subdivision require specification.
Cobertura 2.2 | 01 · Jardim de inverno | SHEET | Vidro / Normalglas | 8 mm nominal glass; safety glazing and panel subdivision require specification.
Cobertura 3.2 | 01 · Jardim de inverno | SHEET | Vidro / Normalglas | 8 mm nominal glass; safety glazing and panel subdivision require specification.
Cobertura 4.2 | 01 · Jardim de inverno | SHEET | Vidro / Normalglas | 8 mm nominal glass; safety glazing and panel subdivision require specification.
Cobertura 5.2 | 01 · Jardim de inverno | SHEET | Vidro / Normalglas | 8 mm nominal glass; safety glazing and panel subdivision require specification.
Cobertura 6.2 | 01 · Jardim de inverno | SHEET | Vidro / Normalglas | 8 mm nominal glass; safety glazing and panel subdivision require specification.
Cobertura 7.2 | 01 · Jardim de inverno | SHEET | Vidro / Normalglas | 8 mm nominal glass; safety glazing and panel subdivision require specification.
Cobertura 8.2 | 01 · Jardim de inverno | SHEET | Vidro / Normalglas | 8 mm nominal glass; safety glazing and panel subdivision require specification.
Cobertura 1.3 | 01 · Jardim de inverno | SHEET | Vidro / Normalglas | 8 mm nominal glass; safety glazing and panel subdivision require specification.
Cobertura 2.3 | 01 · Jardim de inverno | SHEET | Vidro / Normalglas | 8 mm nominal glass; safety glazing and panel subdivision require specification.
Cobertura 3.3 | 01 · Jardim de inverno | SHEET | Vidro / Normalglas | 8 mm nominal glass; safety glazing and panel subdivision require specification.
Cobertura 4.3 | 01 · Jardim de inverno | SHEET | Vidro / Normalglas | 8 mm nominal glass; safety glazing and panel subdivision require specification.
Cobertura 5.3 | 01 · Jardim de inverno | SHEET | Vidro / Normalglas | 8 mm nominal glass; safety glazing and panel subdivision require specification.
Cobertura 6.3 | 01 · Jardim de inverno | SHEET | Vidro / Normalglas | 8 mm nominal glass; safety glazing and panel subdivision require specification.
Cobertura 7.3 | 01 · Jardim de inverno | SHEET | Vidro / Normalglas | 8 mm nominal glass; safety glazing and panel subdivision require specification.
Cobertura 8.3 | 01 · Jardim de inverno | SHEET | Vidro / Normalglas | 8 mm nominal glass; safety glazing and panel subdivision require specification.
Cobertura 1.4 | 01 · Jardim de inverno | SHEET | Vidro / Normalglas | 8 mm nominal glass; safety glazing and panel subdivision require specification.
Cobertura 2.4 | 01 · Jardim de inverno | SHEET | Vidro / Normalglas | 8 mm nominal glass; safety glazing and panel subdivision require specification.
Cobertura 3.4 | 01 · Jardim de inverno | SHEET | Vidro / Normalglas | 8 mm nominal glass; safety glazing and panel subdivision require specification.
Cobertura 4.4 | 01 · Jardim de inverno | SHEET | Vidro / Normalglas | 8 mm nominal glass; safety glazing and panel subdivision require specification.
Cobertura 5.4 | 01 · Jardim de inverno | SHEET | Vidro / Normalglas | 8 mm nominal glass; safety glazing and panel subdivision require specification.
Cobertura 6.4 | 01 · Jardim de inverno | SHEET | Vidro / Normalglas | 8 mm nominal glass; safety glazing and panel subdivision require specification.
Cobertura 7.4 | 01 · Jardim de inverno | SHEET | Vidro / Normalglas | 8 mm nominal glass; safety glazing and panel subdivision require specification.
Cobertura 8.4 | 01 · Jardim de inverno | SHEET | Vidro / Normalglas | 8 mm nominal glass; safety glazing and panel subdivision require specification.
Cobertura 1.5 | 01 · Jardim de inverno | SHEET | Vidro / Normalglas | 8 mm nominal glass; safety glazing and panel subdivision require specification.
Cobertura 2.5 | 01 · Jardim de inverno | SHEET | Vidro / Normalglas | 8 mm nominal glass; safety glazing and panel subdivision require specification.
Cobertura 3.5 | 01 · Jardim de inverno | SHEET | Vidro / Normalglas | 8 mm nominal glass; safety glazing and panel subdivision require specification.
Cobertura 4.5 | 01 · Jardim de inverno | SHEET | Vidro / Normalglas | 8 mm nominal glass; safety glazing and panel subdivision require specification.
Cobertura 5.5 | 01 · Jardim de inverno | SHEET | Vidro / Normalglas | 8 mm nominal glass; safety glazing and panel subdivision require specification.
Cobertura 6.5 | 01 · Jardim de inverno | SHEET | Vidro / Normalglas | 8 mm nominal glass; safety glazing and panel subdivision require specification.
Cobertura 7.5 | 01 · Jardim de inverno | SHEET | Vidro / Normalglas | 8 mm nominal glass; safety glazing and panel subdivision require specification.
Cobertura 8.5 | 01 · Jardim de inverno | SHEET | Vidro / Normalglas | 8 mm nominal glass; safety glazing and panel subdivision require specification.
Cobertura 1.6 | 01 · Jardim de inverno | SHEET | Vidro / Normalglas | 8 mm nominal glass; safety glazing and panel subdivision require specification.
Cobertura 2.6 | 01 · Jardim de inverno | SHEET | Vidro / Normalglas | 8 mm nominal glass; safety glazing and panel subdivision require specification.
Cobertura 3.6 | 01 · Jardim de inverno | SHEET | Vidro / Normalglas | 8 mm nominal glass; safety glazing and panel subdivision require specification.
Cobertura 4.6 | 01 · Jardim de inverno | SHEET | Vidro / Normalglas | 8 mm nominal glass; safety glazing and panel subdivision require specification.
Cobertura 5.6 | 01 · Jardim de inverno | SHEET | Vidro / Normalglas | 8 mm nominal glass; safety glazing and panel subdivision require specification.
Cobertura 6.6 | 01 · Jardim de inverno | SHEET | Vidro / Normalglas | 8 mm nominal glass; safety glazing and panel subdivision require specification.
Cobertura 7.6 | 01 · Jardim de inverno | SHEET | Vidro / Normalglas | 8 mm nominal glass; safety glazing and panel subdivision require specification.
Cobertura 8.6 | 01 · Jardim de inverno | SHEET | Vidro / Normalglas | 8 mm nominal glass; safety glazing and panel subdivision require specification.
Cobertura 1.7 | 01 · Jardim de inverno | SHEET | Vidro / Normalglas | 8 mm nominal glass; safety glazing and panel subdivision require specification.
Cobertura 2.7 | 01 · Jardim de inverno | SHEET | Vidro / Normalglas | 8 mm nominal glass; safety glazing and panel subdivision require specification.
Cobertura 3.7 | 01 · Jardim de inverno | SHEET | Vidro / Normalglas | 8 mm nominal glass; safety glazing and panel subdivision require specification.
Cobertura 4.7 | 01 · Jardim de inverno | SHEET | Vidro / Normalglas | 8 mm nominal glass; safety glazing and panel subdivision require specification.
Cobertura 5.7 | 01 · Jardim de inverno | SHEET | Vidro / Normalglas | 8 mm nominal glass; safety glazing and panel subdivision require specification.
Cobertura 6.7 | 01 · Jardim de inverno | SHEET | Vidro / Normalglas | 8 mm nominal glass; safety glazing and panel subdivision require specification.
Cobertura 7.7 | 01 · Jardim de inverno | SHEET | Vidro / Normalglas | 8 mm nominal glass; safety glazing and panel subdivision require specification.
Cobertura 8.7 | 01 · Jardim de inverno | SHEET | Vidro / Normalglas | 8 mm nominal glass; safety glazing and panel subdivision require specification.
Cobertura 1.8 | 01 · Jardim de inverno | SHEET | Vidro / Normalglas | 8 mm nominal glass; safety glazing and panel subdivision require specification.
Cobertura 2.8 | 01 · Jardim de inverno | SHEET | Vidro / Normalglas | 8 mm nominal glass; safety glazing and panel subdivision require specification.
Cobertura 3.8 | 01 · Jardim de inverno | SHEET | Vidro / Normalglas | 8 mm nominal glass; safety glazing and panel subdivision require specification.
Cobertura 4.8 | 01 · Jardim de inverno | SHEET | Vidro / Normalglas | 8 mm nominal glass; safety glazing and panel subdivision require specification.
Cobertura 5.8 | 01 · Jardim de inverno | SHEET | Vidro / Normalglas | 8 mm nominal glass; safety glazing and panel subdivision require specification.
Cobertura 6.8 | 01 · Jardim de inverno | SHEET | Vidro / Normalglas | 8 mm nominal glass; safety glazing and panel subdivision require specification.
Cobertura 7.8 | 01 · Jardim de inverno | SHEET | Vidro / Normalglas | 8 mm nominal glass; safety glazing and panel subdivision require specification.
Cobertura 8.8 | 01 · Jardim de inverno | SHEET | Vidro / Normalglas | 8 mm nominal glass; safety glazing and panel subdivision require specification.
Cobertura 1.9 | 01 · Jardim de inverno | SHEET | Vidro / Normalglas | 8 mm nominal glass; safety glazing and panel subdivision require specification.
Cobertura 2.9 | 01 · Jardim de inverno | SHEET | Vidro / Normalglas | 8 mm nominal glass; safety glazing and panel subdivision require specification.
Cobertura 3.9 | 01 · Jardim de inverno | SHEET | Vidro / Normalglas | 8 mm nominal glass; safety glazing and panel subdivision require specification.
Cobertura 4.9 | 01 · Jardim de inverno | SHEET | Vidro / Normalglas | 8 mm nominal glass; safety glazing and panel subdivision require specification.
Cobertura 5.9 | 01 · Jardim de inverno | SHEET | Vidro / Normalglas | 8 mm nominal glass; safety glazing and panel subdivision require specification.
Cobertura 6.9 | 01 · Jardim de inverno | SHEET | Vidro / Normalglas | 8 mm nominal glass; safety glazing and panel subdivision require specification.
Cobertura 7.9 | 01 · Jardim de inverno | SHEET | Vidro / Normalglas | 8 mm nominal glass; safety glazing and panel subdivision require specification.
Cobertura 8.9 | 01 · Jardim de inverno | SHEET | Vidro / Normalglas | 8 mm nominal glass; safety glazing and panel subdivision require specification.
Cobertura 1.10 | 01 · Jardim de inverno | SHEET | Vidro / Normalglas | 8 mm nominal glass; safety glazing and panel subdivision require specification.
Cobertura 2.10 | 01 · Jardim de inverno | SHEET | Vidro / Normalglas | 8 mm nominal glass; safety glazing and panel subdivision require specification.
Cobertura 3.10 | 01 · Jardim de inverno | SHEET | Vidro / Normalglas | 8 mm nominal glass; safety glazing and panel subdivision require specification.
Cobertura 4.10 | 01 · Jardim de inverno | SHEET | Vidro / Normalglas | 8 mm nominal glass; safety glazing and panel subdivision require specification.
Cobertura 5.10 | 01 · Jardim de inverno | SHEET | Vidro / Normalglas | 8 mm nominal glass; safety glazing and panel subdivision require specification.
Cobertura 6.10 | 01 · Jardim de inverno | SHEET | Vidro / Normalglas | 8 mm nominal glass; safety glazing and panel subdivision require specification.
Cobertura 7.10 | 01 · Jardim de inverno | SHEET | Vidro / Normalglas | 8 mm nominal glass; safety glazing and panel subdivision require specification.
Cobertura 8.10 | 01 · Jardim de inverno | SHEET | Vidro / Normalglas | 8 mm nominal glass; safety glazing and panel subdivision require specification.
Cobertura 1.11 | 01 · Jardim de inverno | SHEET | Vidro / Normalglas | 8 mm nominal glass; safety glazing and panel subdivision require specification.
Cobertura 2.11 | 01 · Jardim de inverno | SHEET | Vidro / Normalglas | 8 mm nominal glass; safety glazing and panel subdivision require specification.
Cobertura 3.11 | 01 · Jardim de inverno | SHEET | Vidro / Normalglas | 8 mm nominal glass; safety glazing and panel subdivision require specification.
Cobertura 4.11 | 01 · Jardim de inverno | SHEET | Vidro / Normalglas | 8 mm nominal glass; safety glazing and panel subdivision require specification.
Cobertura 5.11 | 01 · Jardim de inverno | SHEET | Vidro / Normalglas | 8 mm nominal glass; safety glazing and panel subdivision require specification.
Cobertura 6.11 | 01 · Jardim de inverno | SHEET | Vidro / Normalglas | 8 mm nominal glass; safety glazing and panel subdivision require specification.
Cobertura 7.11 | 01 · Jardim de inverno | SHEET | Vidro / Normalglas | 8 mm nominal glass; safety glazing and panel subdivision require specification.
Cobertura 8.11 | 01 · Jardim de inverno | SHEET | Vidro / Normalglas | 8 mm nominal glass; safety glazing and panel subdivision require specification.
Cobertura 1.12 | 01 · Jardim de inverno | SHEET | Vidro / Normalglas | 8 mm nominal glass; safety glazing and panel subdivision require specification.
Cobertura 2.12 | 01 · Jardim de inverno | SHEET | Vidro / Normalglas | 8 mm nominal glass; safety glazing and panel subdivision require specification.
Cobertura 3.12 | 01 · Jardim de inverno | SHEET | Vidro / Normalglas | 8 mm nominal glass; safety glazing and panel subdivision require specification.
Cobertura 4.12 | 01 · Jardim de inverno | SHEET | Vidro / Normalglas | 8 mm nominal glass; safety glazing and panel subdivision require specification.
Cobertura 5.12 | 01 · Jardim de inverno | SHEET | Vidro / Normalglas | 8 mm nominal glass; safety glazing and panel subdivision require specification.
Cobertura 6.12 | 01 · Jardim de inverno | SHEET | Vidro / Normalglas | 8 mm nominal glass; safety glazing and panel subdivision require specification.
Cobertura 7.12 | 01 · Jardim de inverno | SHEET | Vidro / Normalglas | 8 mm nominal glass; safety glazing and panel subdivision require specification.
Cobertura 8.12 | 01 · Jardim de inverno | SHEET | Vidro / Normalglas | 8 mm nominal glass; safety glazing and panel subdivision require specification.
Cobertura 1.13 | 01 · Jardim de inverno | SHEET | Vidro / Normalglas | 8 mm nominal glass; safety glazing and panel subdivision require specification.
Cobertura 2.13 | 01 · Jardim de inverno | SHEET | Vidro / Normalglas | 8 mm nominal glass; safety glazing and panel subdivision require specification.
Cobertura 3.13 | 01 · Jardim de inverno | SHEET | Vidro / Normalglas | 8 mm nominal glass; safety glazing and panel subdivision require specification.
Cobertura 4.13 | 01 · Jardim de inverno | SHEET | Vidro / Normalglas | 8 mm nominal glass; safety glazing and panel subdivision require specification.
Cobertura 5.13 | 01 · Jardim de inverno | SHEET | Vidro / Normalglas | 8 mm nominal glass; safety glazing and panel subdivision require specification.
Cobertura 6.13 | 01 · Jardim de inverno | SHEET | Vidro / Normalglas | 8 mm nominal glass; safety glazing and panel subdivision require specification.
Cobertura 7.13 | 01 · Jardim de inverno | SHEET | Vidro / Normalglas | 8 mm nominal glass; safety glazing and panel subdivision require specification.
Cobertura 8.13 | 01 · Jardim de inverno | SHEET | Vidro / Normalglas | 8 mm nominal glass; safety glazing and panel subdivision require specification.
Cobertura 1.14 | 01 · Jardim de inverno | SHEET | Vidro / Normalglas | 8 mm nominal glass; safety glazing and panel subdivision require specification.
Cobertura 2.14 | 01 · Jardim de inverno | SHEET | Vidro / Normalglas | 8 mm nominal glass; safety glazing and panel subdivision require specification.
Cobertura 3.14 | 01 · Jardim de inverno | SHEET | Vidro / Normalglas | 8 mm nominal glass; safety glazing and panel subdivision require specification.
Cobertura 4.14 | 01 · Jardim de inverno | SHEET | Vidro / Normalglas | 8 mm nominal glass; safety glazing and panel subdivision require specification.
Cobertura 5.14 | 01 · Jardim de inverno | SHEET | Vidro / Normalglas | 8 mm nominal glass; safety glazing and panel subdivision require specification.
Cobertura 6.14 | 01 · Jardim de inverno | SHEET | Vidro / Normalglas | 8 mm nominal glass; safety glazing and panel subdivision require specification.
Cobertura 7.14 | 01 · Jardim de inverno | SHEET | Vidro / Normalglas | 8 mm nominal glass; safety glazing and panel subdivision require specification.
Cobertura 8.14 | 01 · Jardim de inverno | SHEET | Vidro / Normalglas | 8 mm nominal glass; safety glazing and panel subdivision require specification.
Cobertura 1.15 | 01 · Jardim de inverno | SHEET | Vidro / Normalglas | 8 mm nominal glass; safety glazing and panel subdivision require specification.
Cobertura 2.15 | 01 · Jardim de inverno | SHEET | Vidro / Normalglas | 8 mm nominal glass; safety glazing and panel subdivision require specification.
Cobertura 3.15 | 01 · Jardim de inverno | SHEET | Vidro / Normalglas | 8 mm nominal glass; safety glazing and panel subdivision require specification.
Cobertura 4.15 | 01 · Jardim de inverno | SHEET | Vidro / Normalglas | 8 mm nominal glass; safety glazing and panel subdivision require specification.
Cobertura 5.15 | 01 · Jardim de inverno | SHEET | Vidro / Normalglas | 8 mm nominal glass; safety glazing and panel subdivision require specification.
Cobertura 6.15 | 01 · Jardim de inverno | SHEET | Vidro / Normalglas | 8 mm nominal glass; safety glazing and panel subdivision require specification.
Cobertura 7.15 | 01 · Jardim de inverno | SHEET | Vidro / Normalglas | 8 mm nominal glass; safety glazing and panel subdivision require specification.
Cobertura 8.15 | 01 · Jardim de inverno | SHEET | Vidro / Normalglas | 8 mm nominal glass; safety glazing and panel subdivision require specification.
Cobertura 1.16 | 01 · Jardim de inverno | SHEET | Vidro / Normalglas | 8 mm nominal glass; safety glazing and panel subdivision require specification.
Cobertura 2.16 | 01 · Jardim de inverno | SHEET | Vidro / Normalglas | 8 mm nominal glass; safety glazing and panel subdivision require specification.
Cobertura 3.16 | 01 · Jardim de inverno | SHEET | Vidro / Normalglas | 8 mm nominal glass; safety glazing and panel subdivision require specification.
Cobertura 4.16 | 01 · Jardim de inverno | SHEET | Vidro / Normalglas | 8 mm nominal glass; safety glazing and panel subdivision require specification.
Cobertura 5.16 | 01 · Jardim de inverno | SHEET | Vidro / Normalglas | 8 mm nominal glass; safety glazing and panel subdivision require specification.
Cobertura 6.16 | 01 · Jardim de inverno | SHEET | Vidro / Normalglas | 8 mm nominal glass; safety glazing and panel subdivision require specification.
Cobertura 7.16 | 01 · Jardim de inverno | SHEET | Vidro / Normalglas | 8 mm nominal glass; safety glazing and panel subdivision require specification.
Cobertura 8.16 | 01 · Jardim de inverno | SHEET | Vidro / Normalglas | 8 mm nominal glass; safety glazing and panel subdivision require specification.
Cobertura 1.17 | 01 · Jardim de inverno | SHEET | Vidro / Normalglas | 8 mm nominal glass; safety glazing and panel subdivision require specification.
Cobertura 2.17 | 01 · Jardim de inverno | SHEET | Vidro / Normalglas | 8 mm nominal glass; safety glazing and panel subdivision require specification.
Cobertura 3.17 | 01 · Jardim de inverno | SHEET | Vidro / Normalglas | 8 mm nominal glass; safety glazing and panel subdivision require specification.
Cobertura 4.17 | 01 · Jardim de inverno | SHEET | Vidro / Normalglas | 8 mm nominal glass; safety glazing and panel subdivision require specification.
Cobertura 5.17 | 01 · Jardim de inverno | SHEET | Vidro / Normalglas | 8 mm nominal glass; safety glazing and panel subdivision require specification.
Cobertura 6.17 | 01 · Jardim de inverno | SHEET | Vidro / Normalglas | 8 mm nominal glass; safety glazing and panel subdivision require specification.
Cobertura 7.17 | 01 · Jardim de inverno | SHEET | Vidro / Normalglas | 8 mm nominal glass; safety glazing and panel subdivision require specification.
Cobertura 8.17 | 01 · Jardim de inverno | SHEET | Vidro / Normalglas | 8 mm nominal glass; safety glazing and panel subdivision require specification.
2 x Empena da estufa | 01 · Jardim de inverno |  | Vidro / Normalglas
Cisterna · tampa estanque de inspeção | 00 · Habitação e estacionamento | SHEET | Aço galvanizado / Stahl verzinkt | Flush, closed 900 mm maintenance hatch; cover capacity and safe maintenance access to detail. Not a routine entrance.
4 x Pérgola · chapa de ancoragem | 00 · Habitação e estacionamento | SHEET | Aço galvanizado / Stahl verzinkt
9 x Projeção estufa · chapa de ancoragem | 00 · Habitação e estacionamento | SHEET | Aço galvanizado / Stahl verzinkt
2 x Contentor · chapa lateral | 00 · Habitação e estacionamento |  | Contentor · pintura 1
Contentor · chapa de fundo | 00 · Habitação e estacionamento |  | Contentor · pintura 1
2 x Contentor · chapa lateral | 00 · Habitação e estacionamento |  | Contentor · pintura 2
Contentor · chapa de fundo | 00 · Habitação e estacionamento |  | Contentor · pintura 2

# IfcRailing (23)
PredefinedType: GUARDRAIL; Material: Aço pintado / Stahl lackiert
Pset_CasaProvenance - DesignSource: Casa Sobreposta / configuration.json; ReferenceFile: 260617_CasaDFL_Estrutura_Terreno.ifc; ConstructionBasis: DESIGN_ASSUMPTION; Note: Study guard 1.10 m; twin handrails at 0.70 and 0.90 m on ramp; loads and fixings unverified.
Name | In
5 x Guarda perimetral da estufa | 01 · Jardim de inverno
Corrimão sala | 00 · Habitação e estacionamento
Corrimão garagem | 00 · Habitação e estacionamento
5 x Guarda do vazio | 01 · Jardim de inverno
Pódio · guarda sul | 00 · Habitação e estacionamento
Pódio · guarda poente sul | 00 · Habitação e estacionamento
Pódio · guarda poente norte | 00 · Habitação e estacionamento
Pódio · guarda norte | 00 · Habitação e estacionamento
2 x Jardim · corrimão poente | 00 · Habitação e estacionamento
2 x Jardim · guarda do patamar | 00 · Habitação e estacionamento
3 x Varanda · guarda | 00 · Habitação e estacionamento

# IfcRailing: SHEEP_WIRE_FENCE (82)
In: Lares · Rua das Mercês · artigo 4771
PredefinedType: USERDEFINED; Material: Aço galvanizado / Stahl verzinkt
Pset_CasaProvenance - DesignSource: Casa Sobreposta / configuration.json; ReferenceFile: 260617_CasaDFL_Estrutura_Terreno.ifc; ConstructionBasis: DESIGN_ASSUMPTION; Note: R09 concept geometry; dimensions and connections not structurally verified.
Pset_CasaFence - Height_m: 1.5; Mesh: Galvanised sheep netting, graduated line wires, 0.30 m vertical stays; Status: CONCEPT; wire gauge, tensioning and posts to specify
Name | PostSpacing_m
Vedação · rede ovelheira 1.001 | 2.31221
Vedação · rede ovelheira 1.002 | 2.31221
Vedação · rede ovelheira 1.003 | 2.31221
Vedação · rede ovelheira 1.004 | 2.85062
Vedação · rede ovelheira 1.005 | 2.85062
Vedação · rede ovelheira 1.006 | 2.85062
Vedação · rede ovelheira 1.007 | 2.85062
Vedação · rede ovelheira 1.008 | 2.41772
Vedação · rede ovelheira 1.009 | 2.41772
Vedação · rede ovelheira 1.010 | 2.41772
Vedação · rede ovelheira 1.011 | 2.41772
Vedação · rede ovelheira 1.012 | 2.41772
Vedação · rede ovelheira 1.013 | 2.4459
Vedação · rede ovelheira 1.014 | 2.4459
Vedação · rede ovelheira 1.015 | 2.4459
Vedação · rede ovelheira 1.016 | 2.4459
Vedação · rede ovelheira 1.017 | 2.4459
Vedação · rede ovelheira 1.018 | 2.41457
Vedação · rede ovelheira 1.019 | 2.41457
Vedação · rede ovelheira 1.020 | 2.41457
Vedação · rede ovelheira 1.021 | 2.41457
Vedação · rede ovelheira 1.022 | 2.41457
Vedação · rede ovelheira 1.023 | 2.93474
Vedação · rede ovelheira 1.024 | 2.93474
Vedação · rede ovelheira 1.025 | 2.93474
Vedação · rede ovelheira 1.026 | 2.93474
Vedação · rede ovelheira 1.027 | 2.4949
Vedação · rede ovelheira 1.028 | 2.4949
Vedação · rede ovelheira 1.029 | 2.4949
Vedação · rede ovelheira 1.030 | 2.4949
Vedação · rede ovelheira 1.031 | 2.4949
Vedação · rede ovelheira 1.032 | 2.41477
Vedação · rede ovelheira 1.033 | 2.41477
Vedação · rede ovelheira 1.034 | 2.41477
Vedação · rede ovelheira 1.035 | 2.41477
Vedação · rede ovelheira 1.036 | 2.90303
Vedação · rede ovelheira 1.037 | 2.90303
Vedação · rede ovelheira 1.038 | 2.59069
Vedação · rede ovelheira 1.039 | 2.59069
Vedação · rede ovelheira 1.040 | 2.59069
Vedação · rede ovelheira 1.041 | 2.12292
Vedação · rede ovelheira 1.042 | 2.12292
Vedação · rede ovelheira 1.043 | 2.49871
Vedação · rede ovelheira 1.044 | 2.49871
Vedação · rede ovelheira 1.045 | 2.49871
Vedação · rede ovelheira 1.046 | 2.44661
Vedação · rede ovelheira 1.047 | 2.44661
Vedação · rede ovelheira 1.048 | 2.44661
Vedação · rede ovelheira 1.049 | 2.06726
Vedação · rede ovelheira 1.050 | 2.06726
Vedação · rede ovelheira 1.051 | 2.68804
Vedação · rede ovelheira 1.052 | 2.68804
Vedação · rede ovelheira 1.053 | 2.76823
Vedação · rede ovelheira 1.054 | 2.76823
Vedação · rede ovelheira 1.055 | 2.76823
Vedação · rede ovelheira 1.056 | 2.73364
Vedação · rede ovelheira 1.057 | 2.73364
Vedação · rede ovelheira 1.058 | 2.73364
Vedação · rede ovelheira 1.059 | 2.9388
Vedação · rede ovelheira 1.060 | 2.9388
Vedação · rede ovelheira 1.061 | 2.99875
Vedação · rede ovelheira 1.062 | 2.99875
Vedação · rede ovelheira 1.063 | 2.99875
Vedação · rede ovelheira 1.064 | 2.42137
Vedação · rede ovelheira 1.065 | 2.42137
Vedação · rede ovelheira 1.066 | 2.42137
Vedação · rede ovelheira 1.067 | 2.42137
Vedação · rede ovelheira 1.068 | 2.65677
Vedação · rede ovelheira 1.069 | 2.65677
Vedação · rede ovelheira 1.070 | 2.65677
Vedação · rede ovelheira 1.071 | 2.65677
Vedação · rede ovelheira 1.072 | 2.96086
Vedação · rede ovelheira 1.073 | 2.96086
Vedação · rede ovelheira 1.074 | 2.96086
Vedação · rede ovelheira 1.075 | 2.83036
Vedação · rede ovelheira 1.076 | 2.83036
Vedação · rede ovelheira 1.077 | 2.83036
Vedação · rede ovelheira 1.078 | 2.61662
Vedação · rede ovelheira 1.079 | 2.61662
Vedação · rede ovelheira 1.080 | 2.61662
Vedação · rede ovelheira 1.081 | 2.61662
Vedação · rede ovelheira 1.082 | 1.96455

# IfcRoof, Cobertura translúcida da estufa
In: 01 · Jardim de inverno
PredefinedType: BARREL_ROOF; Material: Vidro / Normalglas
Pset_CasaProvenance - DesignSource: Casa Sobreposta / configuration.json; ReferenceFile: 260617_CasaDFL_Estrutura_Terreno.ifc; ConstructionBasis: DESIGN_ASSUMPTION; Note: Configurator Coutras section, scaled to 7.90 m with raised ridge; 8 mm glass and 35 mm ribs are study assumptions.

# IfcSanitaryTerminal (8)
Material: Cerâmica sanitária — esquema
Pset_CasaProvenance - DesignSource: Casa Sobreposta / configuration.json; ReferenceFile: 260617_CasaDFL_Estrutura_Terreno.ifc; ConstructionBasis: DESIGN_ASSUMPTION
Name | In | PredefinedType | Note
Banheira | 00 · Habitação e estacionamento | BATH | Schematic fixture, not a manufacturer object.
Lavatório 1 | 00 · Habitação e estacionamento | WASHHANDBASIN | Schematic fixture, not a manufacturer object.
Lavatório 2 | 00 · Habitação e estacionamento | WASHHANDBASIN | Schematic fixture, not a manufacturer object.
Sanita | 00 · Habitação e estacionamento | TOILETPAN | Schematic fixture, not a manufacturer object.
Bancada de cozinha | 00 · Habitação e estacionamento | TOILETPAN | Schematic fixture, not a manufacturer object.
Lavatório superior | 01 · Jardim de inverno | WASHHANDBASIN
Sanita superior | 01 · Jardim de inverno | TOILETPAN
Duche superior | 01 · Jardim de inverno | SHOWER

# IfcSlab (11)
Pset_CasaProvenance - DesignSource: Casa Sobreposta / configuration.json; ReferenceFile: 260617_CasaDFL_Estrutura_Terreno.ifc
Name | In | PredefinedType | Material | ConstructionBasis
OSB estrutural · 20 mm | 01 · Jardim de inverno | FLOOR | OSB | ADAPTED_REFERENCE | Pset_CasaProvenance - Note: Two real stair voids. Light protective finish assumed; drains and waterproof upstands require detailing.
Cisterna · laje de fundo 200 mm | -01 · Cisterna sob o terraço | BASESLAB | Betão armado / Stahlbeton | DESIGN_ASSUMPTION
Pódio · laje da casa 250 mm | 00 · Habitação e estacionamento | FLOOR | Betão armado / Stahlbeton | DESIGN_ASSUMPTION | Pset_CasaProvenance - Note: Suspended slab on discrete piers and grade beams. Natural slope retained where clear; local shallow excavation where beams meet rising ground. Sizes unverified.
Pódio · terraço e faixa de proteção sul | 00 · Habitação e estacionamento | FLOOR | Betão armado / Stahlbeton | DESIGN_ASSUMPTION | Pset_CasaProvenance - Note: Terrace 40 mm below house. West terrace over void/cistern; shallow local formation to east. Parking is a separate ground-supported pavement.
Estacionamento · pavimento apoiado no solo | 00 · Habitação e estacionamento | BASESLAB | Betão armado / Stahlbeton | DESIGN_ASSUMPTION | Pset_CasaProvenance - Note: R09 concept geometry; dimensions and connections not structurally verified.; Pset_CasaParking - GroundSupported: yes; LongitudinalGrade_percent: 2.5; Crossfall_percent: 4; HouseThresholdStep_m: 0.02; Status: Concept grading; pavement build-up and accessibility to detail
Jardim · patamar poente | 00 · Habitação e estacionamento | LANDING | Betão armado / Stahlbeton | DESIGN_ASSUMPTION
Varanda · faixa poente 1,20 m úteis | 01 · Jardim de inverno | FLOOR | Aço galvanizado / Stahl verzinkt | DESIGN_ASSUMPTION | Pset_CasaProvenance - Note: Open upper gallery; non-slip deck and member connections to design. 1.25 m gross strip, approximately 1.20 m clear.
2 x Contentor · piso ou teto | 00 · Habitação e estacionamento | FLOOR | Contentor · pintura 1 | DESIGN_ASSUMPTION
2 x Contentor · piso ou teto | 00 · Habitação e estacionamento | FLOOR | Contentor · pintura 2 | DESIGN_ASSUMPTION

# IfcStair (3)
In: 00 · Habitação e estacionamento
PredefinedType: STRAIGHT_RUN_STAIR
Pset_CasaProvenance - DesignSource: Casa Sobreposta / configuration.json; ReferenceFile: 260617_CasaDFL_Estrutura_Terreno.ifc
Name | ConstructionBasis | Note
Escada sala | ADAPTED_REFERENCE | Configurator 18 x 0.18 m risers / 17 x 0.265 m goings / 0.70 m width. Steel channels and OSB treads adapted from source.
Escada garagem | ADAPTED_REFERENCE | Configurator 18 x 0.18 m risers / 17 x 0.265 m goings / 0.70 m width. Steel channels and OSB treads adapted from source.
Jardim · escada pela fachada poente | DESIGN_ASSUMPTION | West-facing descent; no south opening. Survey-based concept.

# IfcStairFlight (3)
In: 00 · Habitação e estacionamento
PredefinedType: STRAIGHT
Pset_CasaProvenance - DesignSource: Casa Sobreposta / configuration.json; ReferenceFile: 260617_CasaDFL_Estrutura_Terreno.ifc
Name | NumberOfRisers | NumberOfTreads | RiserHeight (m) | TreadLength (m) | Material | ConstructionBasis
Lanço sala | 18 | 17 | 0.18 | 0.265 | OSB | ADAPTED_REFERENCE
Lanço garagem | 18 | 17 | 0.18 | 0.265 | OSB | ADAPTED_REFERENCE
Jardim · lanço poente | 12 | 11 | 0.159167 | 0.3 | Betão armado / Stahlbeton | DESIGN_ASSUMPTION

# IfcTank: RAINWATER_CISTERN, Cisterna · reservatório pluvial de estudo
In: -01 · Cisterna sob o terraço
PredefinedType: STORAGE
Pset_CasaProvenance - DesignSource: Casa Sobreposta / configuration.json; ReferenceFile: 260617_CasaDFL_Estrutura_Terreno.ifc; ConstructionBasis: DESIGN_ASSUMPTION; Note: Composite concrete vessel; provisional geometry only. No ordinary occupancy or stair access. Water depth and capacity to design.
Pset_CasaCistern - InternalPlanArea_m2: 17.8125; WaterDepthAssumed_m: 2; GeometricWaterVolume_m3: 35.625; SoffitClearanceAboveWater_m: 0.31; Status: Provisional water envelope; hydrostatic, uplift, watertightness, filtration, overflow and maintenance design pending

# IfcWall (17)
Pset_CasaProvenance - DesignSource: Casa Sobreposta / configuration.json; ReferenceFile: 260617_CasaDFL_Estrutura_Terreno.ifc; ConstructionBasis: ADAPTED_REFERENCE
Name | In | Material | OverallThickness_m | SourceModelSkinThicknesses_m | Core_m | Pset_CasaAssembly, Note
Divisória 1 · OSB 22 mm nas duas faces | 00 · Habitação e estacionamento | OSB, Lã mineral / Mineralwolle 2 | Pset_CasaProvenance - Note: Original centreline/door positions preserved; schematic footprint widened 20 mm per side. 22 mm OSB linings; mineral wool core; stud layout not developed.
Divisória 2 · OSB 22 mm nas duas faces | 00 · Habitação e estacionamento | OSB, Lã mineral / Mineralwolle 2 | Pset_CasaProvenance - Note: Original centreline/door positions preserved; schematic footprint widened 20 mm per side. 22 mm OSB linings; mineral wool core; stud layout not developed.
Divisória 3 · OSB 22 mm nas duas faces | 00 · Habitação e estacionamento | OSB, Lã mineral / Mineralwolle 2 | Pset_CasaProvenance - Note: Original centreline/door positions preserved; schematic footprint widened 20 mm per side. 22 mm OSB linings; mineral wool core; stud layout not developed.
Divisória 4 · OSB 22 mm nas duas faces | 00 · Habitação e estacionamento | OSB, Lã mineral / Mineralwolle 2 | Pset_CasaProvenance - Note: Original centreline/door positions preserved; schematic footprint widened 20 mm per side. 22 mm OSB linings; mineral wool core; stud layout not developed.
Fachada norte · sandwich Casa DFL | 00 · Habitação e estacionamento | Aço pintado / Stahl lackiert 0.005 m, Lã mineral / Mineralwolle 2 0.12 m, Aço pintado / Stahl lackiert 0.00516 m | 0.13016 | 0.005 / 0.00516 | 0.12 | Source geometry retained; commercial sheet specification not established.
Separação do estacionamento | 00 · Habitação e estacionamento | Aço pintado / Stahl lackiert 0.005 m, Lã mineral / Mineralwolle 2 0.12 m, Aço pintado / Stahl lackiert 0.00516 m | 0.13016 | 0.005 / 0.00516 | 0.12 | Source geometry retained; commercial sheet specification not established.
